VERSION 5.8 ;
BUSBITCHARS "[]" ;
DIVIDERCHAR "/" ;
UNITS
    DATABASE MICRONS 1000 ;
END UNITS

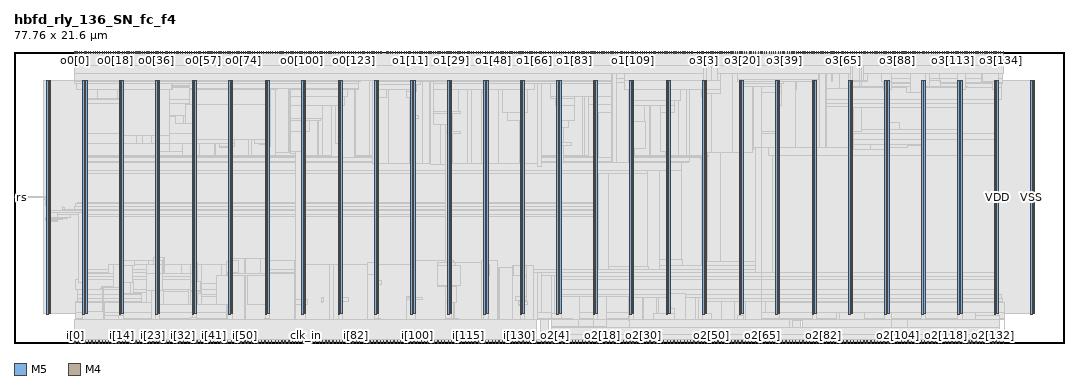
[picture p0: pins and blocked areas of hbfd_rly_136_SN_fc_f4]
MACRO hbfd_rly_136_SN_fc_f4
  FOREIGN hbfd_rly_136_SN_fc_f4 0 0 ;
  CLASS BLOCK ;
  SIZE 77.76 BY 21.6 ;
  PIN clk_in
    DIRECTION INPUT ;
    USE SIGNAL ;
    PORT
      LAYER M5 ;
        RECT  21.6 0 21.624 0.192 ;
    END
  END clk_in
  PIN clk_out0
    DIRECTION OUTPUT ;
    USE SIGNAL ;
    PORT
      LAYER M5 ;
        RECT  15.84 21.408 15.864 21.6 ;
    END
  END clk_out0
  PIN clk_out1
    DIRECTION OUTPUT ;
    USE SIGNAL ;
    PORT
      LAYER M5 ;
        RECT  38.88 21.408 38.904 21.6 ;
    END
  END clk_out1
  PIN clk_out2
    DIRECTION OUTPUT ;
    USE SIGNAL ;
    PORT
      LAYER M5 ;
        RECT  56.16 0 56.184 0.192 ;
    END
  END clk_out2
  PIN clk_out3
    DIRECTION OUTPUT ;
    USE SIGNAL ;
    PORT
      LAYER M5 ;
        RECT  61.92 21.408 61.944 21.6 ;
    END
  END clk_out3
  PIN i[0]
    DIRECTION INPUT ;
    USE SIGNAL ;
    PORT
      LAYER M5 ;
        RECT  4.512 0 4.536 0.192 ;
    END
  END i[0]
  PIN i[100]
    DIRECTION INPUT ;
    USE SIGNAL ;
    PORT
      LAYER M5 ;
        RECT  29.856 0 29.88 0.192 ;
    END
  END i[100]
  PIN i[101]
    DIRECTION INPUT ;
    USE SIGNAL ;
    PORT
      LAYER M5 ;
        RECT  30.144 0 30.168 0.192 ;
    END
  END i[101]
  PIN i[102]
    DIRECTION INPUT ;
    USE SIGNAL ;
    PORT
      LAYER M5 ;
        RECT  30.384 0 30.408 0.192 ;
    END
  END i[102]
  PIN i[103]
    DIRECTION INPUT ;
    USE SIGNAL ;
    PORT
      LAYER M5 ;
        RECT  30.624 0 30.648 0.192 ;
    END
  END i[103]
  PIN i[104]
    DIRECTION INPUT ;
    USE SIGNAL ;
    PORT
      LAYER M5 ;
        RECT  30.864 0 30.888 0.192 ;
    END
  END i[104]
  PIN i[105]
    DIRECTION INPUT ;
    USE SIGNAL ;
    PORT
      LAYER M5 ;
        RECT  31.152 0 31.176 0.192 ;
    END
  END i[105]
  PIN i[106]
    DIRECTION INPUT ;
    USE SIGNAL ;
    PORT
      LAYER M5 ;
        RECT  31.392 0 31.416 0.192 ;
    END
  END i[106]
  PIN i[107]
    DIRECTION INPUT ;
    USE SIGNAL ;
    PORT
      LAYER M5 ;
        RECT  31.632 0 31.656 0.192 ;
    END
  END i[107]
  PIN i[108]
    DIRECTION INPUT ;
    USE SIGNAL ;
    PORT
      LAYER M5 ;
        RECT  31.872 0 31.896 0.192 ;
    END
  END i[108]
  PIN i[109]
    DIRECTION INPUT ;
    USE SIGNAL ;
    PORT
      LAYER M5 ;
        RECT  32.16 0 32.184 0.192 ;
    END
  END i[109]
  PIN i[10]
    DIRECTION INPUT ;
    USE SIGNAL ;
    PORT
      LAYER M5 ;
        RECT  7.008 0 7.032 0.192 ;
    END
  END i[10]
  PIN i[110]
    DIRECTION INPUT ;
    USE SIGNAL ;
    PORT
      LAYER M5 ;
        RECT  32.4 0 32.424 0.192 ;
    END
  END i[110]
  PIN i[111]
    DIRECTION INPUT ;
    USE SIGNAL ;
    PORT
      LAYER M5 ;
        RECT  32.64 0 32.664 0.192 ;
    END
  END i[111]
  PIN i[112]
    DIRECTION INPUT ;
    USE SIGNAL ;
    PORT
      LAYER M5 ;
        RECT  32.88 0 32.904 0.192 ;
    END
  END i[112]
  PIN i[113]
    DIRECTION INPUT ;
    USE SIGNAL ;
    PORT
      LAYER M5 ;
        RECT  33.12 0 33.144 0.192 ;
    END
  END i[113]
  PIN i[114]
    DIRECTION INPUT ;
    USE SIGNAL ;
    PORT
      LAYER M5 ;
        RECT  33.408 0 33.432 0.192 ;
    END
  END i[114]
  PIN i[115]
    DIRECTION INPUT ;
    USE SIGNAL ;
    PORT
      LAYER M5 ;
        RECT  33.648 0 33.672 0.192 ;
    END
  END i[115]
  PIN i[116]
    DIRECTION INPUT ;
    USE SIGNAL ;
    PORT
      LAYER M5 ;
        RECT  33.888 0 33.912 0.192 ;
    END
  END i[116]
  PIN i[117]
    DIRECTION INPUT ;
    USE SIGNAL ;
    PORT
      LAYER M5 ;
        RECT  34.128 0 34.152 0.192 ;
    END
  END i[117]
  PIN i[118]
    DIRECTION INPUT ;
    USE SIGNAL ;
    PORT
      LAYER M5 ;
        RECT  34.416 0 34.44 0.192 ;
    END
  END i[118]
  PIN i[119]
    DIRECTION INPUT ;
    USE SIGNAL ;
    PORT
      LAYER M5 ;
        RECT  34.656 0 34.68 0.192 ;
    END
  END i[119]
  PIN i[11]
    DIRECTION INPUT ;
    USE SIGNAL ;
    PORT
      LAYER M5 ;
        RECT  7.248 0 7.272 0.192 ;
    END
  END i[11]
  PIN i[120]
    DIRECTION INPUT ;
    USE SIGNAL ;
    PORT
      LAYER M5 ;
        RECT  34.896 0 34.92 0.192 ;
    END
  END i[120]
  PIN i[121]
    DIRECTION INPUT ;
    USE SIGNAL ;
    PORT
      LAYER M5 ;
        RECT  35.136 0 35.16 0.192 ;
    END
  END i[121]
  PIN i[122]
    DIRECTION INPUT ;
    USE SIGNAL ;
    PORT
      LAYER M5 ;
        RECT  35.424 0 35.448 0.192 ;
    END
  END i[122]
  PIN i[123]
    DIRECTION INPUT ;
    USE SIGNAL ;
    PORT
      LAYER M5 ;
        RECT  35.664 0 35.688 0.192 ;
    END
  END i[123]
  PIN i[124]
    DIRECTION INPUT ;
    USE SIGNAL ;
    PORT
      LAYER M5 ;
        RECT  35.904 0 35.928 0.192 ;
    END
  END i[124]
  PIN i[125]
    DIRECTION INPUT ;
    USE SIGNAL ;
    PORT
      LAYER M5 ;
        RECT  36.144 0 36.168 0.192 ;
    END
  END i[125]
  PIN i[126]
    DIRECTION INPUT ;
    USE SIGNAL ;
    PORT
      LAYER M5 ;
        RECT  36.384 0 36.408 0.192 ;
    END
  END i[126]
  PIN i[127]
    DIRECTION INPUT ;
    USE SIGNAL ;
    PORT
      LAYER M5 ;
        RECT  36.672 0 36.696 0.192 ;
    END
  END i[127]
  PIN i[128]
    DIRECTION INPUT ;
    USE SIGNAL ;
    PORT
      LAYER M5 ;
        RECT  36.912 0 36.936 0.192 ;
    END
  END i[128]
  PIN i[129]
    DIRECTION INPUT ;
    USE SIGNAL ;
    PORT
      LAYER M5 ;
        RECT  37.152 0 37.176 0.192 ;
    END
  END i[129]
  PIN i[12]
    DIRECTION INPUT ;
    USE SIGNAL ;
    PORT
      LAYER M5 ;
        RECT  7.536 0 7.56 0.192 ;
    END
  END i[12]
  PIN i[130]
    DIRECTION INPUT ;
    USE SIGNAL ;
    PORT
      LAYER M5 ;
        RECT  37.392 0 37.416 0.192 ;
    END
  END i[130]
  PIN i[131]
    DIRECTION INPUT ;
    USE SIGNAL ;
    PORT
      LAYER M5 ;
        RECT  37.68 0 37.704 0.192 ;
    END
  END i[131]
  PIN i[132]
    DIRECTION INPUT ;
    USE SIGNAL ;
    PORT
      LAYER M5 ;
        RECT  37.92 0 37.944 0.192 ;
    END
  END i[132]
  PIN i[133]
    DIRECTION INPUT ;
    USE SIGNAL ;
    PORT
      LAYER M5 ;
        RECT  38.16 0 38.184 0.192 ;
    END
  END i[133]
  PIN i[134]
    DIRECTION INPUT ;
    USE SIGNAL ;
    PORT
      LAYER M5 ;
        RECT  38.4 0 38.424 0.192 ;
    END
  END i[134]
  PIN i[135]
    DIRECTION INPUT ;
    USE SIGNAL ;
    PORT
      LAYER M5 ;
        RECT  38.688 0 38.712 0.192 ;
    END
  END i[135]
  PIN i[13]
    DIRECTION INPUT ;
    USE SIGNAL ;
    PORT
      LAYER M5 ;
        RECT  7.776 0 7.8 0.192 ;
    END
  END i[13]
  PIN i[14]
    DIRECTION INPUT ;
    USE SIGNAL ;
    PORT
      LAYER M5 ;
        RECT  8.016 0 8.04 0.192 ;
    END
  END i[14]
  PIN i[15]
    DIRECTION INPUT ;
    USE SIGNAL ;
    PORT
      LAYER M5 ;
        RECT  8.256 0 8.28 0.192 ;
    END
  END i[15]
  PIN i[16]
    DIRECTION INPUT ;
    USE SIGNAL ;
    PORT
      LAYER M5 ;
        RECT  8.544 0 8.568 0.192 ;
    END
  END i[16]
  PIN i[17]
    DIRECTION INPUT ;
    USE SIGNAL ;
    PORT
      LAYER M5 ;
        RECT  8.784 0 8.808 0.192 ;
    END
  END i[17]
  PIN i[18]
    DIRECTION INPUT ;
    USE SIGNAL ;
    PORT
      LAYER M5 ;
        RECT  9.024 0 9.048 0.192 ;
    END
  END i[18]
  PIN i[19]
    DIRECTION INPUT ;
    USE SIGNAL ;
    PORT
      LAYER M5 ;
        RECT  9.264 0 9.288 0.192 ;
    END
  END i[19]
  PIN i[1]
    DIRECTION INPUT ;
    USE SIGNAL ;
    PORT
      LAYER M5 ;
        RECT  4.752 0 4.776 0.192 ;
    END
  END i[1]
  PIN i[20]
    DIRECTION INPUT ;
    USE SIGNAL ;
    PORT
      LAYER M5 ;
        RECT  9.552 0 9.576 0.192 ;
    END
  END i[20]
  PIN i[21]
    DIRECTION INPUT ;
    USE SIGNAL ;
    PORT
      LAYER M5 ;
        RECT  9.792 0 9.816 0.192 ;
    END
  END i[21]
  PIN i[22]
    DIRECTION INPUT ;
    USE SIGNAL ;
    PORT
      LAYER M5 ;
        RECT  10.032 0 10.056 0.192 ;
    END
  END i[22]
  PIN i[23]
    DIRECTION INPUT ;
    USE SIGNAL ;
    PORT
      LAYER M5 ;
        RECT  10.272 0 10.296 0.192 ;
    END
  END i[23]
  PIN i[24]
    DIRECTION INPUT ;
    USE SIGNAL ;
    PORT
      LAYER M5 ;
        RECT  10.56 0 10.584 0.192 ;
    END
  END i[24]
  PIN i[25]
    DIRECTION INPUT ;
    USE SIGNAL ;
    PORT
      LAYER M5 ;
        RECT  10.8 0 10.824 0.192 ;
    END
  END i[25]
  PIN i[26]
    DIRECTION INPUT ;
    USE SIGNAL ;
    PORT
      LAYER M5 ;
        RECT  11.04 0 11.064 0.192 ;
    END
  END i[26]
  PIN i[27]
    DIRECTION INPUT ;
    USE SIGNAL ;
    PORT
      LAYER M5 ;
        RECT  11.28 0 11.304 0.192 ;
    END
  END i[27]
  PIN i[28]
    DIRECTION INPUT ;
    USE SIGNAL ;
    PORT
      LAYER M5 ;
        RECT  11.52 0 11.544 0.192 ;
    END
  END i[28]
  PIN i[29]
    DIRECTION INPUT ;
    USE SIGNAL ;
    PORT
      LAYER M5 ;
        RECT  11.808 0 11.832 0.192 ;
    END
  END i[29]
  PIN i[2]
    DIRECTION INPUT ;
    USE SIGNAL ;
    PORT
      LAYER M5 ;
        RECT  4.992 0 5.016 0.192 ;
    END
  END i[2]
  PIN i[30]
    DIRECTION INPUT ;
    USE SIGNAL ;
    PORT
      LAYER M5 ;
        RECT  12.048 0 12.072 0.192 ;
    END
  END i[30]
  PIN i[31]
    DIRECTION INPUT ;
    USE SIGNAL ;
    PORT
      LAYER M5 ;
        RECT  12.288 0 12.312 0.192 ;
    END
  END i[31]
  PIN i[32]
    DIRECTION INPUT ;
    USE SIGNAL ;
    PORT
      LAYER M5 ;
        RECT  12.528 0 12.552 0.192 ;
    END
  END i[32]
  PIN i[33]
    DIRECTION INPUT ;
    USE SIGNAL ;
    PORT
      LAYER M5 ;
        RECT  12.816 0 12.84 0.192 ;
    END
  END i[33]
  PIN i[34]
    DIRECTION INPUT ;
    USE SIGNAL ;
    PORT
      LAYER M5 ;
        RECT  13.056 0 13.08 0.192 ;
    END
  END i[34]
  PIN i[35]
    DIRECTION INPUT ;
    USE SIGNAL ;
    PORT
      LAYER M5 ;
        RECT  13.296 0 13.32 0.192 ;
    END
  END i[35]
  PIN i[36]
    DIRECTION INPUT ;
    USE SIGNAL ;
    PORT
      LAYER M5 ;
        RECT  13.536 0 13.56 0.192 ;
    END
  END i[36]
  PIN i[37]
    DIRECTION INPUT ;
    USE SIGNAL ;
    PORT
      LAYER M5 ;
        RECT  13.824 0 13.848 0.192 ;
    END
  END i[37]
  PIN i[38]
    DIRECTION INPUT ;
    USE SIGNAL ;
    PORT
      LAYER M5 ;
        RECT  14.064 0 14.088 0.192 ;
    END
  END i[38]
  PIN i[39]
    DIRECTION INPUT ;
    USE SIGNAL ;
    PORT
      LAYER M5 ;
        RECT  14.304 0 14.328 0.192 ;
    END
  END i[39]
  PIN i[3]
    DIRECTION INPUT ;
    USE SIGNAL ;
    PORT
      LAYER M5 ;
        RECT  5.28 0 5.304 0.192 ;
    END
  END i[3]
  PIN i[40]
    DIRECTION INPUT ;
    USE SIGNAL ;
    PORT
      LAYER M5 ;
        RECT  14.544 0 14.568 0.192 ;
    END
  END i[40]
  PIN i[41]
    DIRECTION INPUT ;
    USE SIGNAL ;
    PORT
      LAYER M5 ;
        RECT  14.784 0 14.808 0.192 ;
    END
  END i[41]
  PIN i[42]
    DIRECTION INPUT ;
    USE SIGNAL ;
    PORT
      LAYER M5 ;
        RECT  15.072 0 15.096 0.192 ;
    END
  END i[42]
  PIN i[43]
    DIRECTION INPUT ;
    USE SIGNAL ;
    PORT
      LAYER M5 ;
        RECT  15.312 0 15.336 0.192 ;
    END
  END i[43]
  PIN i[44]
    DIRECTION INPUT ;
    USE SIGNAL ;
    PORT
      LAYER M5 ;
        RECT  15.552 0 15.576 0.192 ;
    END
  END i[44]
  PIN i[45]
    DIRECTION INPUT ;
    USE SIGNAL ;
    PORT
      LAYER M5 ;
        RECT  15.792 0 15.816 0.192 ;
    END
  END i[45]
  PIN i[46]
    DIRECTION INPUT ;
    USE SIGNAL ;
    PORT
      LAYER M5 ;
        RECT  16.08 0 16.104 0.192 ;
    END
  END i[46]
  PIN i[47]
    DIRECTION INPUT ;
    USE SIGNAL ;
    PORT
      LAYER M5 ;
        RECT  16.32 0 16.344 0.192 ;
    END
  END i[47]
  PIN i[48]
    DIRECTION INPUT ;
    USE SIGNAL ;
    PORT
      LAYER M5 ;
        RECT  16.56 0 16.584 0.192 ;
    END
  END i[48]
  PIN i[49]
    DIRECTION INPUT ;
    USE SIGNAL ;
    PORT
      LAYER M5 ;
        RECT  16.8 0 16.824 0.192 ;
    END
  END i[49]
  PIN i[4]
    DIRECTION INPUT ;
    USE SIGNAL ;
    PORT
      LAYER M5 ;
        RECT  5.52 0 5.544 0.192 ;
    END
  END i[4]
  PIN i[50]
    DIRECTION INPUT ;
    USE SIGNAL ;
    PORT
      LAYER M5 ;
        RECT  17.088 0 17.112 0.192 ;
    END
  END i[50]
  PIN i[51]
    DIRECTION INPUT ;
    USE SIGNAL ;
    PORT
      LAYER M5 ;
        RECT  17.328 0 17.352 0.192 ;
    END
  END i[51]
  PIN i[52]
    DIRECTION INPUT ;
    USE SIGNAL ;
    PORT
      LAYER M5 ;
        RECT  17.568 0 17.592 0.192 ;
    END
  END i[52]
  PIN i[53]
    DIRECTION INPUT ;
    USE SIGNAL ;
    PORT
      LAYER M5 ;
        RECT  17.808 0 17.832 0.192 ;
    END
  END i[53]
  PIN i[54]
    DIRECTION INPUT ;
    USE SIGNAL ;
    PORT
      LAYER M5 ;
        RECT  18.048 0 18.072 0.192 ;
    END
  END i[54]
  PIN i[55]
    DIRECTION INPUT ;
    USE SIGNAL ;
    PORT
      LAYER M5 ;
        RECT  18.336 0 18.36 0.192 ;
    END
  END i[55]
  PIN i[56]
    DIRECTION INPUT ;
    USE SIGNAL ;
    PORT
      LAYER M5 ;
        RECT  18.576 0 18.6 0.192 ;
    END
  END i[56]
  PIN i[57]
    DIRECTION INPUT ;
    USE SIGNAL ;
    PORT
      LAYER M5 ;
        RECT  18.816 0 18.84 0.192 ;
    END
  END i[57]
  PIN i[58]
    DIRECTION INPUT ;
    USE SIGNAL ;
    PORT
      LAYER M5 ;
        RECT  19.056 0 19.08 0.192 ;
    END
  END i[58]
  PIN i[59]
    DIRECTION INPUT ;
    USE SIGNAL ;
    PORT
      LAYER M5 ;
        RECT  19.344 0 19.368 0.192 ;
    END
  END i[59]
  PIN i[5]
    DIRECTION INPUT ;
    USE SIGNAL ;
    PORT
      LAYER M5 ;
        RECT  5.76 0 5.784 0.192 ;
    END
  END i[5]
  PIN i[60]
    DIRECTION INPUT ;
    USE SIGNAL ;
    PORT
      LAYER M5 ;
        RECT  19.584 0 19.608 0.192 ;
    END
  END i[60]
  PIN i[61]
    DIRECTION INPUT ;
    USE SIGNAL ;
    PORT
      LAYER M5 ;
        RECT  19.824 0 19.848 0.192 ;
    END
  END i[61]
  PIN i[62]
    DIRECTION INPUT ;
    USE SIGNAL ;
    PORT
      LAYER M5 ;
        RECT  20.064 0 20.088 0.192 ;
    END
  END i[62]
  PIN i[63]
    DIRECTION INPUT ;
    USE SIGNAL ;
    PORT
      LAYER M5 ;
        RECT  20.352 0 20.376 0.192 ;
    END
  END i[63]
  PIN i[64]
    DIRECTION INPUT ;
    USE SIGNAL ;
    PORT
      LAYER M5 ;
        RECT  20.592 0 20.616 0.192 ;
    END
  END i[64]
  PIN i[65]
    DIRECTION INPUT ;
    USE SIGNAL ;
    PORT
      LAYER M5 ;
        RECT  20.832 0 20.856 0.192 ;
    END
  END i[65]
  PIN i[66]
    DIRECTION INPUT ;
    USE SIGNAL ;
    PORT
      LAYER M5 ;
        RECT  21.072 0 21.096 0.192 ;
    END
  END i[66]
  PIN i[67]
    DIRECTION INPUT ;
    USE SIGNAL ;
    PORT
      LAYER M5 ;
        RECT  21.36 0 21.384 0.192 ;
    END
  END i[67]
  PIN i[68]
    DIRECTION INPUT ;
    USE SIGNAL ;
    PORT
      LAYER M5 ;
        RECT  21.84 0 21.864 0.192 ;
    END
  END i[68]
  PIN i[69]
    DIRECTION INPUT ;
    USE SIGNAL ;
    PORT
      LAYER M5 ;
        RECT  22.08 0 22.104 0.192 ;
    END
  END i[69]
  PIN i[6]
    DIRECTION INPUT ;
    USE SIGNAL ;
    PORT
      LAYER M5 ;
        RECT  6 0 6.024 0.192 ;
    END
  END i[6]
  PIN i[70]
    DIRECTION INPUT ;
    USE SIGNAL ;
    PORT
      LAYER M5 ;
        RECT  22.32 0 22.344 0.192 ;
    END
  END i[70]
  PIN i[71]
    DIRECTION INPUT ;
    USE SIGNAL ;
    PORT
      LAYER M5 ;
        RECT  22.608 0 22.632 0.192 ;
    END
  END i[71]
  PIN i[72]
    DIRECTION INPUT ;
    USE SIGNAL ;
    PORT
      LAYER M5 ;
        RECT  22.848 0 22.872 0.192 ;
    END
  END i[72]
  PIN i[73]
    DIRECTION INPUT ;
    USE SIGNAL ;
    PORT
      LAYER M5 ;
        RECT  23.088 0 23.112 0.192 ;
    END
  END i[73]
  PIN i[74]
    DIRECTION INPUT ;
    USE SIGNAL ;
    PORT
      LAYER M5 ;
        RECT  23.328 0 23.352 0.192 ;
    END
  END i[74]
  PIN i[75]
    DIRECTION INPUT ;
    USE SIGNAL ;
    PORT
      LAYER M5 ;
        RECT  23.616 0 23.64 0.192 ;
    END
  END i[75]
  PIN i[76]
    DIRECTION INPUT ;
    USE SIGNAL ;
    PORT
      LAYER M5 ;
        RECT  23.856 0 23.88 0.192 ;
    END
  END i[76]
  PIN i[77]
    DIRECTION INPUT ;
    USE SIGNAL ;
    PORT
      LAYER M5 ;
        RECT  24.096 0 24.12 0.192 ;
    END
  END i[77]
  PIN i[78]
    DIRECTION INPUT ;
    USE SIGNAL ;
    PORT
      LAYER M5 ;
        RECT  24.336 0 24.36 0.192 ;
    END
  END i[78]
  PIN i[79]
    DIRECTION INPUT ;
    USE SIGNAL ;
    PORT
      LAYER M5 ;
        RECT  24.624 0 24.648 0.192 ;
    END
  END i[79]
  PIN i[7]
    DIRECTION INPUT ;
    USE SIGNAL ;
    PORT
      LAYER M5 ;
        RECT  6.288 0 6.312 0.192 ;
    END
  END i[7]
  PIN i[80]
    DIRECTION INPUT ;
    USE SIGNAL ;
    PORT
      LAYER M5 ;
        RECT  24.864 0 24.888 0.192 ;
    END
  END i[80]
  PIN i[81]
    DIRECTION INPUT ;
    USE SIGNAL ;
    PORT
      LAYER M5 ;
        RECT  25.104 0 25.128 0.192 ;
    END
  END i[81]
  PIN i[82]
    DIRECTION INPUT ;
    USE SIGNAL ;
    PORT
      LAYER M5 ;
        RECT  25.344 0 25.368 0.192 ;
    END
  END i[82]
  PIN i[83]
    DIRECTION INPUT ;
    USE SIGNAL ;
    PORT
      LAYER M5 ;
        RECT  25.584 0 25.608 0.192 ;
    END
  END i[83]
  PIN i[84]
    DIRECTION INPUT ;
    USE SIGNAL ;
    PORT
      LAYER M5 ;
        RECT  25.872 0 25.896 0.192 ;
    END
  END i[84]
  PIN i[85]
    DIRECTION INPUT ;
    USE SIGNAL ;
    PORT
      LAYER M5 ;
        RECT  26.112 0 26.136 0.192 ;
    END
  END i[85]
  PIN i[86]
    DIRECTION INPUT ;
    USE SIGNAL ;
    PORT
      LAYER M5 ;
        RECT  26.352 0 26.376 0.192 ;
    END
  END i[86]
  PIN i[87]
    DIRECTION INPUT ;
    USE SIGNAL ;
    PORT
      LAYER M5 ;
        RECT  26.592 0 26.616 0.192 ;
    END
  END i[87]
  PIN i[88]
    DIRECTION INPUT ;
    USE SIGNAL ;
    PORT
      LAYER M5 ;
        RECT  26.88 0 26.904 0.192 ;
    END
  END i[88]
  PIN i[89]
    DIRECTION INPUT ;
    USE SIGNAL ;
    PORT
      LAYER M5 ;
        RECT  27.12 0 27.144 0.192 ;
    END
  END i[89]
  PIN i[8]
    DIRECTION INPUT ;
    USE SIGNAL ;
    PORT
      LAYER M5 ;
        RECT  6.528 0 6.552 0.192 ;
    END
  END i[8]
  PIN i[90]
    DIRECTION INPUT ;
    USE SIGNAL ;
    PORT
      LAYER M5 ;
        RECT  27.36 0 27.384 0.192 ;
    END
  END i[90]
  PIN i[91]
    DIRECTION INPUT ;
    USE SIGNAL ;
    PORT
      LAYER M5 ;
        RECT  27.6 0 27.624 0.192 ;
    END
  END i[91]
  PIN i[92]
    DIRECTION INPUT ;
    USE SIGNAL ;
    PORT
      LAYER M5 ;
        RECT  27.888 0 27.912 0.192 ;
    END
  END i[92]
  PIN i[93]
    DIRECTION INPUT ;
    USE SIGNAL ;
    PORT
      LAYER M5 ;
        RECT  28.128 0 28.152 0.192 ;
    END
  END i[93]
  PIN i[94]
    DIRECTION INPUT ;
    USE SIGNAL ;
    PORT
      LAYER M5 ;
        RECT  28.368 0 28.392 0.192 ;
    END
  END i[94]
  PIN i[95]
    DIRECTION INPUT ;
    USE SIGNAL ;
    PORT
      LAYER M5 ;
        RECT  28.608 0 28.632 0.192 ;
    END
  END i[95]
  PIN i[96]
    DIRECTION INPUT ;
    USE SIGNAL ;
    PORT
      LAYER M5 ;
        RECT  28.896 0 28.92 0.192 ;
    END
  END i[96]
  PIN i[97]
    DIRECTION INPUT ;
    USE SIGNAL ;
    PORT
      LAYER M5 ;
        RECT  29.136 0 29.16 0.192 ;
    END
  END i[97]
  PIN i[98]
    DIRECTION INPUT ;
    USE SIGNAL ;
    PORT
      LAYER M5 ;
        RECT  29.376 0 29.4 0.192 ;
    END
  END i[98]
  PIN i[99]
    DIRECTION INPUT ;
    USE SIGNAL ;
    PORT
      LAYER M5 ;
        RECT  29.616 0 29.64 0.192 ;
    END
  END i[99]
  PIN i[9]
    DIRECTION INPUT ;
    USE SIGNAL ;
    PORT
      LAYER M5 ;
        RECT  6.768 0 6.792 0.192 ;
    END
  END i[9]
  PIN o0[0]
    DIRECTION OUTPUT ;
    USE SIGNAL ;
    PORT
      LAYER M5 ;
        RECT  4.512 21.408 4.536 21.6 ;
    END
  END o0[0]
  PIN o0[100]
    DIRECTION OUTPUT ;
    USE SIGNAL ;
    PORT
      LAYER M5 ;
        RECT  21.312 21.408 21.336 21.6 ;
    END
  END o0[100]
  PIN o0[101]
    DIRECTION OUTPUT ;
    USE SIGNAL ;
    PORT
      LAYER M5 ;
        RECT  21.504 21.408 21.528 21.6 ;
    END
  END o0[101]
  PIN o0[102]
    DIRECTION OUTPUT ;
    USE SIGNAL ;
    PORT
      LAYER M5 ;
        RECT  21.648 21.408 21.672 21.6 ;
    END
  END o0[102]
  PIN o0[103]
    DIRECTION OUTPUT ;
    USE SIGNAL ;
    PORT
      LAYER M5 ;
        RECT  21.84 21.408 21.864 21.6 ;
    END
  END o0[103]
  PIN o0[104]
    DIRECTION OUTPUT ;
    USE SIGNAL ;
    PORT
      LAYER M5 ;
        RECT  21.984 21.408 22.008 21.6 ;
    END
  END o0[104]
  PIN o0[105]
    DIRECTION OUTPUT ;
    USE SIGNAL ;
    PORT
      LAYER M5 ;
        RECT  22.176 21.408 22.2 21.6 ;
    END
  END o0[105]
  PIN o0[106]
    DIRECTION OUTPUT ;
    USE SIGNAL ;
    PORT
      LAYER M5 ;
        RECT  22.32 21.408 22.344 21.6 ;
    END
  END o0[106]
  PIN o0[107]
    DIRECTION OUTPUT ;
    USE SIGNAL ;
    PORT
      LAYER M5 ;
        RECT  22.464 21.408 22.488 21.6 ;
    END
  END o0[107]
  PIN o0[108]
    DIRECTION OUTPUT ;
    USE SIGNAL ;
    PORT
      LAYER M5 ;
        RECT  22.656 21.408 22.68 21.6 ;
    END
  END o0[108]
  PIN o0[109]
    DIRECTION OUTPUT ;
    USE SIGNAL ;
    PORT
      LAYER M5 ;
        RECT  22.8 21.408 22.824 21.6 ;
    END
  END o0[109]
  PIN o0[10]
    DIRECTION OUTPUT ;
    USE SIGNAL ;
    PORT
      LAYER M5 ;
        RECT  6.192 21.408 6.216 21.6 ;
    END
  END o0[10]
  PIN o0[110]
    DIRECTION OUTPUT ;
    USE SIGNAL ;
    PORT
      LAYER M5 ;
        RECT  22.992 21.408 23.016 21.6 ;
    END
  END o0[110]
  PIN o0[111]
    DIRECTION OUTPUT ;
    USE SIGNAL ;
    PORT
      LAYER M5 ;
        RECT  23.136 21.408 23.16 21.6 ;
    END
  END o0[111]
  PIN o0[112]
    DIRECTION OUTPUT ;
    USE SIGNAL ;
    PORT
      LAYER M5 ;
        RECT  23.328 21.408 23.352 21.6 ;
    END
  END o0[112]
  PIN o0[113]
    DIRECTION OUTPUT ;
    USE SIGNAL ;
    PORT
      LAYER M5 ;
        RECT  23.472 21.408 23.496 21.6 ;
    END
  END o0[113]
  PIN o0[114]
    DIRECTION OUTPUT ;
    USE SIGNAL ;
    PORT
      LAYER M5 ;
        RECT  23.664 21.408 23.688 21.6 ;
    END
  END o0[114]
  PIN o0[115]
    DIRECTION OUTPUT ;
    USE SIGNAL ;
    PORT
      LAYER M5 ;
        RECT  23.808 21.408 23.832 21.6 ;
    END
  END o0[115]
  PIN o0[116]
    DIRECTION OUTPUT ;
    USE SIGNAL ;
    PORT
      LAYER M5 ;
        RECT  24 21.408 24.024 21.6 ;
    END
  END o0[116]
  PIN o0[117]
    DIRECTION OUTPUT ;
    USE SIGNAL ;
    PORT
      LAYER M5 ;
        RECT  24.144 21.408 24.168 21.6 ;
    END
  END o0[117]
  PIN o0[118]
    DIRECTION OUTPUT ;
    USE SIGNAL ;
    PORT
      LAYER M5 ;
        RECT  24.336 21.408 24.36 21.6 ;
    END
  END o0[118]
  PIN o0[119]
    DIRECTION OUTPUT ;
    USE SIGNAL ;
    PORT
      LAYER M5 ;
        RECT  24.48 21.408 24.504 21.6 ;
    END
  END o0[119]
  PIN o0[11]
    DIRECTION OUTPUT ;
    USE SIGNAL ;
    PORT
      LAYER M5 ;
        RECT  6.336 21.408 6.36 21.6 ;
    END
  END o0[11]
  PIN o0[120]
    DIRECTION OUTPUT ;
    USE SIGNAL ;
    PORT
      LAYER M5 ;
        RECT  24.672 21.408 24.696 21.6 ;
    END
  END o0[120]
  PIN o0[121]
    DIRECTION OUTPUT ;
    USE SIGNAL ;
    PORT
      LAYER M5 ;
        RECT  24.816 21.408 24.84 21.6 ;
    END
  END o0[121]
  PIN o0[122]
    DIRECTION OUTPUT ;
    USE SIGNAL ;
    PORT
      LAYER M5 ;
        RECT  24.96 21.408 24.984 21.6 ;
    END
  END o0[122]
  PIN o0[123]
    DIRECTION OUTPUT ;
    USE SIGNAL ;
    PORT
      LAYER M5 ;
        RECT  25.152 21.408 25.176 21.6 ;
    END
  END o0[123]
  PIN o0[124]
    DIRECTION OUTPUT ;
    USE SIGNAL ;
    PORT
      LAYER M5 ;
        RECT  25.296 21.408 25.32 21.6 ;
    END
  END o0[124]
  PIN o0[125]
    DIRECTION OUTPUT ;
    USE SIGNAL ;
    PORT
      LAYER M5 ;
        RECT  25.488 21.408 25.512 21.6 ;
    END
  END o0[125]
  PIN o0[126]
    DIRECTION OUTPUT ;
    USE SIGNAL ;
    PORT
      LAYER M5 ;
        RECT  25.632 21.408 25.656 21.6 ;
    END
  END o0[126]
  PIN o0[127]
    DIRECTION OUTPUT ;
    USE SIGNAL ;
    PORT
      LAYER M5 ;
        RECT  25.824 21.408 25.848 21.6 ;
    END
  END o0[127]
  PIN o0[128]
    DIRECTION OUTPUT ;
    USE SIGNAL ;
    PORT
      LAYER M5 ;
        RECT  25.968 21.408 25.992 21.6 ;
    END
  END o0[128]
  PIN o0[129]
    DIRECTION OUTPUT ;
    USE SIGNAL ;
    PORT
      LAYER M5 ;
        RECT  26.16 21.408 26.184 21.6 ;
    END
  END o0[129]
  PIN o0[12]
    DIRECTION OUTPUT ;
    USE SIGNAL ;
    PORT
      LAYER M5 ;
        RECT  6.528 21.408 6.552 21.6 ;
    END
  END o0[12]
  PIN o0[130]
    DIRECTION OUTPUT ;
    USE SIGNAL ;
    PORT
      LAYER M5 ;
        RECT  26.304 21.408 26.328 21.6 ;
    END
  END o0[130]
  PIN o0[131]
    DIRECTION OUTPUT ;
    USE SIGNAL ;
    PORT
      LAYER M5 ;
        RECT  26.496 21.408 26.52 21.6 ;
    END
  END o0[131]
  PIN o0[132]
    DIRECTION OUTPUT ;
    USE SIGNAL ;
    PORT
      LAYER M5 ;
        RECT  26.64 21.408 26.664 21.6 ;
    END
  END o0[132]
  PIN o0[133]
    DIRECTION OUTPUT ;
    USE SIGNAL ;
    PORT
      LAYER M5 ;
        RECT  26.832 21.408 26.856 21.6 ;
    END
  END o0[133]
  PIN o0[134]
    DIRECTION OUTPUT ;
    USE SIGNAL ;
    PORT
      LAYER M5 ;
        RECT  26.976 21.408 27 21.6 ;
    END
  END o0[134]
  PIN o0[135]
    DIRECTION OUTPUT ;
    USE SIGNAL ;
    PORT
      LAYER M5 ;
        RECT  27.168 21.408 27.192 21.6 ;
    END
  END o0[135]
  PIN o0[13]
    DIRECTION OUTPUT ;
    USE SIGNAL ;
    PORT
      LAYER M5 ;
        RECT  6.672 21.408 6.696 21.6 ;
    END
  END o0[13]
  PIN o0[14]
    DIRECTION OUTPUT ;
    USE SIGNAL ;
    PORT
      LAYER M5 ;
        RECT  6.816 21.408 6.84 21.6 ;
    END
  END o0[14]
  PIN o0[15]
    DIRECTION OUTPUT ;
    USE SIGNAL ;
    PORT
      LAYER M5 ;
        RECT  7.008 21.408 7.032 21.6 ;
    END
  END o0[15]
  PIN o0[16]
    DIRECTION OUTPUT ;
    USE SIGNAL ;
    PORT
      LAYER M5 ;
        RECT  7.152 21.408 7.176 21.6 ;
    END
  END o0[16]
  PIN o0[17]
    DIRECTION OUTPUT ;
    USE SIGNAL ;
    PORT
      LAYER M5 ;
        RECT  7.344 21.408 7.368 21.6 ;
    END
  END o0[17]
  PIN o0[18]
    DIRECTION OUTPUT ;
    USE SIGNAL ;
    PORT
      LAYER M5 ;
        RECT  7.488 21.408 7.512 21.6 ;
    END
  END o0[18]
  PIN o0[19]
    DIRECTION OUTPUT ;
    USE SIGNAL ;
    PORT
      LAYER M5 ;
        RECT  7.68 21.408 7.704 21.6 ;
    END
  END o0[19]
  PIN o0[1]
    DIRECTION OUTPUT ;
    USE SIGNAL ;
    PORT
      LAYER M5 ;
        RECT  4.656 21.408 4.68 21.6 ;
    END
  END o0[1]
  PIN o0[20]
    DIRECTION OUTPUT ;
    USE SIGNAL ;
    PORT
      LAYER M5 ;
        RECT  7.824 21.408 7.848 21.6 ;
    END
  END o0[20]
  PIN o0[21]
    DIRECTION OUTPUT ;
    USE SIGNAL ;
    PORT
      LAYER M5 ;
        RECT  8.016 21.408 8.04 21.6 ;
    END
  END o0[21]
  PIN o0[22]
    DIRECTION OUTPUT ;
    USE SIGNAL ;
    PORT
      LAYER M5 ;
        RECT  8.16 21.408 8.184 21.6 ;
    END
  END o0[22]
  PIN o0[23]
    DIRECTION OUTPUT ;
    USE SIGNAL ;
    PORT
      LAYER M5 ;
        RECT  8.352 21.408 8.376 21.6 ;
    END
  END o0[23]
  PIN o0[24]
    DIRECTION OUTPUT ;
    USE SIGNAL ;
    PORT
      LAYER M5 ;
        RECT  8.496 21.408 8.52 21.6 ;
    END
  END o0[24]
  PIN o0[25]
    DIRECTION OUTPUT ;
    USE SIGNAL ;
    PORT
      LAYER M5 ;
        RECT  8.688 21.408 8.712 21.6 ;
    END
  END o0[25]
  PIN o0[26]
    DIRECTION OUTPUT ;
    USE SIGNAL ;
    PORT
      LAYER M5 ;
        RECT  8.832 21.408 8.856 21.6 ;
    END
  END o0[26]
  PIN o0[27]
    DIRECTION OUTPUT ;
    USE SIGNAL ;
    PORT
      LAYER M5 ;
        RECT  9.024 21.408 9.048 21.6 ;
    END
  END o0[27]
  PIN o0[28]
    DIRECTION OUTPUT ;
    USE SIGNAL ;
    PORT
      LAYER M5 ;
        RECT  9.168 21.408 9.192 21.6 ;
    END
  END o0[28]
  PIN o0[29]
    DIRECTION OUTPUT ;
    USE SIGNAL ;
    PORT
      LAYER M5 ;
        RECT  9.312 21.408 9.336 21.6 ;
    END
  END o0[29]
  PIN o0[2]
    DIRECTION OUTPUT ;
    USE SIGNAL ;
    PORT
      LAYER M5 ;
        RECT  4.848 21.408 4.872 21.6 ;
    END
  END o0[2]
  PIN o0[30]
    DIRECTION OUTPUT ;
    USE SIGNAL ;
    PORT
      LAYER M5 ;
        RECT  9.504 21.408 9.528 21.6 ;
    END
  END o0[30]
  PIN o0[31]
    DIRECTION OUTPUT ;
    USE SIGNAL ;
    PORT
      LAYER M5 ;
        RECT  9.648 21.408 9.672 21.6 ;
    END
  END o0[31]
  PIN o0[32]
    DIRECTION OUTPUT ;
    USE SIGNAL ;
    PORT
      LAYER M5 ;
        RECT  9.84 21.408 9.864 21.6 ;
    END
  END o0[32]
  PIN o0[33]
    DIRECTION OUTPUT ;
    USE SIGNAL ;
    PORT
      LAYER M5 ;
        RECT  9.984 21.408 10.008 21.6 ;
    END
  END o0[33]
  PIN o0[34]
    DIRECTION OUTPUT ;
    USE SIGNAL ;
    PORT
      LAYER M5 ;
        RECT  10.176 21.408 10.2 21.6 ;
    END
  END o0[34]
  PIN o0[35]
    DIRECTION OUTPUT ;
    USE SIGNAL ;
    PORT
      LAYER M5 ;
        RECT  10.32 21.408 10.344 21.6 ;
    END
  END o0[35]
  PIN o0[36]
    DIRECTION OUTPUT ;
    USE SIGNAL ;
    PORT
      LAYER M5 ;
        RECT  10.512 21.408 10.536 21.6 ;
    END
  END o0[36]
  PIN o0[37]
    DIRECTION OUTPUT ;
    USE SIGNAL ;
    PORT
      LAYER M5 ;
        RECT  10.656 21.408 10.68 21.6 ;
    END
  END o0[37]
  PIN o0[38]
    DIRECTION OUTPUT ;
    USE SIGNAL ;
    PORT
      LAYER M5 ;
        RECT  10.848 21.408 10.872 21.6 ;
    END
  END o0[38]
  PIN o0[39]
    DIRECTION OUTPUT ;
    USE SIGNAL ;
    PORT
      LAYER M5 ;
        RECT  10.992 21.408 11.016 21.6 ;
    END
  END o0[39]
  PIN o0[3]
    DIRECTION OUTPUT ;
    USE SIGNAL ;
    PORT
      LAYER M5 ;
        RECT  4.992 21.408 5.016 21.6 ;
    END
  END o0[3]
  PIN o0[40]
    DIRECTION OUTPUT ;
    USE SIGNAL ;
    PORT
      LAYER M5 ;
        RECT  11.184 21.408 11.208 21.6 ;
    END
  END o0[40]
  PIN o0[41]
    DIRECTION OUTPUT ;
    USE SIGNAL ;
    PORT
      LAYER M5 ;
        RECT  11.328 21.408 11.352 21.6 ;
    END
  END o0[41]
  PIN o0[42]
    DIRECTION OUTPUT ;
    USE SIGNAL ;
    PORT
      LAYER M5 ;
        RECT  11.52 21.408 11.544 21.6 ;
    END
  END o0[42]
  PIN o0[43]
    DIRECTION OUTPUT ;
    USE SIGNAL ;
    PORT
      LAYER M5 ;
        RECT  11.664 21.408 11.688 21.6 ;
    END
  END o0[43]
  PIN o0[44]
    DIRECTION OUTPUT ;
    USE SIGNAL ;
    PORT
      LAYER M5 ;
        RECT  11.856 21.408 11.88 21.6 ;
    END
  END o0[44]
  PIN o0[45]
    DIRECTION OUTPUT ;
    USE SIGNAL ;
    PORT
      LAYER M5 ;
        RECT  12 21.408 12.024 21.6 ;
    END
  END o0[45]
  PIN o0[46]
    DIRECTION OUTPUT ;
    USE SIGNAL ;
    PORT
      LAYER M5 ;
        RECT  12.144 21.408 12.168 21.6 ;
    END
  END o0[46]
  PIN o0[47]
    DIRECTION OUTPUT ;
    USE SIGNAL ;
    PORT
      LAYER M5 ;
        RECT  12.336 21.408 12.36 21.6 ;
    END
  END o0[47]
  PIN o0[48]
    DIRECTION OUTPUT ;
    USE SIGNAL ;
    PORT
      LAYER M5 ;
        RECT  12.48 21.408 12.504 21.6 ;
    END
  END o0[48]
  PIN o0[49]
    DIRECTION OUTPUT ;
    USE SIGNAL ;
    PORT
      LAYER M5 ;
        RECT  12.672 21.408 12.696 21.6 ;
    END
  END o0[49]
  PIN o0[4]
    DIRECTION OUTPUT ;
    USE SIGNAL ;
    PORT
      LAYER M5 ;
        RECT  5.184 21.408 5.208 21.6 ;
    END
  END o0[4]
  PIN o0[50]
    DIRECTION OUTPUT ;
    USE SIGNAL ;
    PORT
      LAYER M5 ;
        RECT  12.816 21.408 12.84 21.6 ;
    END
  END o0[50]
  PIN o0[51]
    DIRECTION OUTPUT ;
    USE SIGNAL ;
    PORT
      LAYER M5 ;
        RECT  13.008 21.408 13.032 21.6 ;
    END
  END o0[51]
  PIN o0[52]
    DIRECTION OUTPUT ;
    USE SIGNAL ;
    PORT
      LAYER M5 ;
        RECT  13.152 21.408 13.176 21.6 ;
    END
  END o0[52]
  PIN o0[53]
    DIRECTION OUTPUT ;
    USE SIGNAL ;
    PORT
      LAYER M5 ;
        RECT  13.344 21.408 13.368 21.6 ;
    END
  END o0[53]
  PIN o0[54]
    DIRECTION OUTPUT ;
    USE SIGNAL ;
    PORT
      LAYER M5 ;
        RECT  13.488 21.408 13.512 21.6 ;
    END
  END o0[54]
  PIN o0[55]
    DIRECTION OUTPUT ;
    USE SIGNAL ;
    PORT
      LAYER M5 ;
        RECT  13.68 21.408 13.704 21.6 ;
    END
  END o0[55]
  PIN o0[56]
    DIRECTION OUTPUT ;
    USE SIGNAL ;
    PORT
      LAYER M5 ;
        RECT  13.824 21.408 13.848 21.6 ;
    END
  END o0[56]
  PIN o0[57]
    DIRECTION OUTPUT ;
    USE SIGNAL ;
    PORT
      LAYER M5 ;
        RECT  14.016 21.408 14.04 21.6 ;
    END
  END o0[57]
  PIN o0[58]
    DIRECTION OUTPUT ;
    USE SIGNAL ;
    PORT
      LAYER M5 ;
        RECT  14.16 21.408 14.184 21.6 ;
    END
  END o0[58]
  PIN o0[59]
    DIRECTION OUTPUT ;
    USE SIGNAL ;
    PORT
      LAYER M5 ;
        RECT  14.352 21.408 14.376 21.6 ;
    END
  END o0[59]
  PIN o0[5]
    DIRECTION OUTPUT ;
    USE SIGNAL ;
    PORT
      LAYER M5 ;
        RECT  5.328 21.408 5.352 21.6 ;
    END
  END o0[5]
  PIN o0[60]
    DIRECTION OUTPUT ;
    USE SIGNAL ;
    PORT
      LAYER M5 ;
        RECT  14.496 21.408 14.52 21.6 ;
    END
  END o0[60]
  PIN o0[61]
    DIRECTION OUTPUT ;
    USE SIGNAL ;
    PORT
      LAYER M5 ;
        RECT  14.64 21.408 14.664 21.6 ;
    END
  END o0[61]
  PIN o0[62]
    DIRECTION OUTPUT ;
    USE SIGNAL ;
    PORT
      LAYER M5 ;
        RECT  14.832 21.408 14.856 21.6 ;
    END
  END o0[62]
  PIN o0[63]
    DIRECTION OUTPUT ;
    USE SIGNAL ;
    PORT
      LAYER M5 ;
        RECT  14.976 21.408 15 21.6 ;
    END
  END o0[63]
  PIN o0[64]
    DIRECTION OUTPUT ;
    USE SIGNAL ;
    PORT
      LAYER M5 ;
        RECT  15.168 21.408 15.192 21.6 ;
    END
  END o0[64]
  PIN o0[65]
    DIRECTION OUTPUT ;
    USE SIGNAL ;
    PORT
      LAYER M5 ;
        RECT  15.312 21.408 15.336 21.6 ;
    END
  END o0[65]
  PIN o0[66]
    DIRECTION OUTPUT ;
    USE SIGNAL ;
    PORT
      LAYER M5 ;
        RECT  15.504 21.408 15.528 21.6 ;
    END
  END o0[66]
  PIN o0[67]
    DIRECTION OUTPUT ;
    USE SIGNAL ;
    PORT
      LAYER M5 ;
        RECT  15.648 21.408 15.672 21.6 ;
    END
  END o0[67]
  PIN o0[68]
    DIRECTION OUTPUT ;
    USE SIGNAL ;
    PORT
      LAYER M5 ;
        RECT  15.984 21.408 16.008 21.6 ;
    END
  END o0[68]
  PIN o0[69]
    DIRECTION OUTPUT ;
    USE SIGNAL ;
    PORT
      LAYER M5 ;
        RECT  16.176 21.408 16.2 21.6 ;
    END
  END o0[69]
  PIN o0[6]
    DIRECTION OUTPUT ;
    USE SIGNAL ;
    PORT
      LAYER M5 ;
        RECT  5.52 21.408 5.544 21.6 ;
    END
  END o0[6]
  PIN o0[70]
    DIRECTION OUTPUT ;
    USE SIGNAL ;
    PORT
      LAYER M5 ;
        RECT  16.32 21.408 16.344 21.6 ;
    END
  END o0[70]
  PIN o0[71]
    DIRECTION OUTPUT ;
    USE SIGNAL ;
    PORT
      LAYER M5 ;
        RECT  16.512 21.408 16.536 21.6 ;
    END
  END o0[71]
  PIN o0[72]
    DIRECTION OUTPUT ;
    USE SIGNAL ;
    PORT
      LAYER M5 ;
        RECT  16.656 21.408 16.68 21.6 ;
    END
  END o0[72]
  PIN o0[73]
    DIRECTION OUTPUT ;
    USE SIGNAL ;
    PORT
      LAYER M5 ;
        RECT  16.848 21.408 16.872 21.6 ;
    END
  END o0[73]
  PIN o0[74]
    DIRECTION OUTPUT ;
    USE SIGNAL ;
    PORT
      LAYER M5 ;
        RECT  16.992 21.408 17.016 21.6 ;
    END
  END o0[74]
  PIN o0[75]
    DIRECTION OUTPUT ;
    USE SIGNAL ;
    PORT
      LAYER M5 ;
        RECT  17.136 21.408 17.16 21.6 ;
    END
  END o0[75]
  PIN o0[76]
    DIRECTION OUTPUT ;
    USE SIGNAL ;
    PORT
      LAYER M5 ;
        RECT  17.328 21.408 17.352 21.6 ;
    END
  END o0[76]
  PIN o0[77]
    DIRECTION OUTPUT ;
    USE SIGNAL ;
    PORT
      LAYER M5 ;
        RECT  17.472 21.408 17.496 21.6 ;
    END
  END o0[77]
  PIN o0[78]
    DIRECTION OUTPUT ;
    USE SIGNAL ;
    PORT
      LAYER M5 ;
        RECT  17.664 21.408 17.688 21.6 ;
    END
  END o0[78]
  PIN o0[79]
    DIRECTION OUTPUT ;
    USE SIGNAL ;
    PORT
      LAYER M5 ;
        RECT  17.808 21.408 17.832 21.6 ;
    END
  END o0[79]
  PIN o0[7]
    DIRECTION OUTPUT ;
    USE SIGNAL ;
    PORT
      LAYER M5 ;
        RECT  5.664 21.408 5.688 21.6 ;
    END
  END o0[7]
  PIN o0[80]
    DIRECTION OUTPUT ;
    USE SIGNAL ;
    PORT
      LAYER M5 ;
        RECT  18 21.408 18.024 21.6 ;
    END
  END o0[80]
  PIN o0[81]
    DIRECTION OUTPUT ;
    USE SIGNAL ;
    PORT
      LAYER M5 ;
        RECT  18.144 21.408 18.168 21.6 ;
    END
  END o0[81]
  PIN o0[82]
    DIRECTION OUTPUT ;
    USE SIGNAL ;
    PORT
      LAYER M5 ;
        RECT  18.336 21.408 18.36 21.6 ;
    END
  END o0[82]
  PIN o0[83]
    DIRECTION OUTPUT ;
    USE SIGNAL ;
    PORT
      LAYER M5 ;
        RECT  18.48 21.408 18.504 21.6 ;
    END
  END o0[83]
  PIN o0[84]
    DIRECTION OUTPUT ;
    USE SIGNAL ;
    PORT
      LAYER M5 ;
        RECT  18.672 21.408 18.696 21.6 ;
    END
  END o0[84]
  PIN o0[85]
    DIRECTION OUTPUT ;
    USE SIGNAL ;
    PORT
      LAYER M5 ;
        RECT  18.816 21.408 18.84 21.6 ;
    END
  END o0[85]
  PIN o0[86]
    DIRECTION OUTPUT ;
    USE SIGNAL ;
    PORT
      LAYER M5 ;
        RECT  19.008 21.408 19.032 21.6 ;
    END
  END o0[86]
  PIN o0[87]
    DIRECTION OUTPUT ;
    USE SIGNAL ;
    PORT
      LAYER M5 ;
        RECT  19.152 21.408 19.176 21.6 ;
    END
  END o0[87]
  PIN o0[88]
    DIRECTION OUTPUT ;
    USE SIGNAL ;
    PORT
      LAYER M5 ;
        RECT  19.344 21.408 19.368 21.6 ;
    END
  END o0[88]
  PIN o0[89]
    DIRECTION OUTPUT ;
    USE SIGNAL ;
    PORT
      LAYER M5 ;
        RECT  19.488 21.408 19.512 21.6 ;
    END
  END o0[89]
  PIN o0[8]
    DIRECTION OUTPUT ;
    USE SIGNAL ;
    PORT
      LAYER M5 ;
        RECT  5.856 21.408 5.88 21.6 ;
    END
  END o0[8]
  PIN o0[90]
    DIRECTION OUTPUT ;
    USE SIGNAL ;
    PORT
      LAYER M5 ;
        RECT  19.68 21.408 19.704 21.6 ;
    END
  END o0[90]
  PIN o0[91]
    DIRECTION OUTPUT ;
    USE SIGNAL ;
    PORT
      LAYER M5 ;
        RECT  19.824 21.408 19.848 21.6 ;
    END
  END o0[91]
  PIN o0[92]
    DIRECTION OUTPUT ;
    USE SIGNAL ;
    PORT
      LAYER M5 ;
        RECT  19.968 21.408 19.992 21.6 ;
    END
  END o0[92]
  PIN o0[93]
    DIRECTION OUTPUT ;
    USE SIGNAL ;
    PORT
      LAYER M5 ;
        RECT  20.16 21.408 20.184 21.6 ;
    END
  END o0[93]
  PIN o0[94]
    DIRECTION OUTPUT ;
    USE SIGNAL ;
    PORT
      LAYER M5 ;
        RECT  20.304 21.408 20.328 21.6 ;
    END
  END o0[94]
  PIN o0[95]
    DIRECTION OUTPUT ;
    USE SIGNAL ;
    PORT
      LAYER M5 ;
        RECT  20.496 21.408 20.52 21.6 ;
    END
  END o0[95]
  PIN o0[96]
    DIRECTION OUTPUT ;
    USE SIGNAL ;
    PORT
      LAYER M5 ;
        RECT  20.64 21.408 20.664 21.6 ;
    END
  END o0[96]
  PIN o0[97]
    DIRECTION OUTPUT ;
    USE SIGNAL ;
    PORT
      LAYER M5 ;
        RECT  20.832 21.408 20.856 21.6 ;
    END
  END o0[97]
  PIN o0[98]
    DIRECTION OUTPUT ;
    USE SIGNAL ;
    PORT
      LAYER M5 ;
        RECT  20.976 21.408 21 21.6 ;
    END
  END o0[98]
  PIN o0[99]
    DIRECTION OUTPUT ;
    USE SIGNAL ;
    PORT
      LAYER M5 ;
        RECT  21.168 21.408 21.192 21.6 ;
    END
  END o0[99]
  PIN o0[9]
    DIRECTION OUTPUT ;
    USE SIGNAL ;
    PORT
      LAYER M5 ;
        RECT  6 21.408 6.024 21.6 ;
    END
  END o0[9]
  PIN o1[0]
    DIRECTION OUTPUT ;
    USE SIGNAL ;
    PORT
      LAYER M5 ;
        RECT  27.552 21.408 27.576 21.6 ;
    END
  END o1[0]
  PIN o1[100]
    DIRECTION OUTPUT ;
    USE SIGNAL ;
    PORT
      LAYER M5 ;
        RECT  44.352 21.408 44.376 21.6 ;
    END
  END o1[100]
  PIN o1[101]
    DIRECTION OUTPUT ;
    USE SIGNAL ;
    PORT
      LAYER M5 ;
        RECT  44.544 21.408 44.568 21.6 ;
    END
  END o1[101]
  PIN o1[102]
    DIRECTION OUTPUT ;
    USE SIGNAL ;
    PORT
      LAYER M5 ;
        RECT  44.688 21.408 44.712 21.6 ;
    END
  END o1[102]
  PIN o1[103]
    DIRECTION OUTPUT ;
    USE SIGNAL ;
    PORT
      LAYER M5 ;
        RECT  44.88 21.408 44.904 21.6 ;
    END
  END o1[103]
  PIN o1[104]
    DIRECTION OUTPUT ;
    USE SIGNAL ;
    PORT
      LAYER M5 ;
        RECT  45.024 21.408 45.048 21.6 ;
    END
  END o1[104]
  PIN o1[105]
    DIRECTION OUTPUT ;
    USE SIGNAL ;
    PORT
      LAYER M5 ;
        RECT  45.216 21.408 45.24 21.6 ;
    END
  END o1[105]
  PIN o1[106]
    DIRECTION OUTPUT ;
    USE SIGNAL ;
    PORT
      LAYER M5 ;
        RECT  45.36 21.408 45.384 21.6 ;
    END
  END o1[106]
  PIN o1[107]
    DIRECTION OUTPUT ;
    USE SIGNAL ;
    PORT
      LAYER M5 ;
        RECT  45.504 21.408 45.528 21.6 ;
    END
  END o1[107]
  PIN o1[108]
    DIRECTION OUTPUT ;
    USE SIGNAL ;
    PORT
      LAYER M5 ;
        RECT  45.696 21.408 45.72 21.6 ;
    END
  END o1[108]
  PIN o1[109]
    DIRECTION OUTPUT ;
    USE SIGNAL ;
    PORT
      LAYER M5 ;
        RECT  45.84 21.408 45.864 21.6 ;
    END
  END o1[109]
  PIN o1[10]
    DIRECTION OUTPUT ;
    USE SIGNAL ;
    PORT
      LAYER M5 ;
        RECT  29.232 21.408 29.256 21.6 ;
    END
  END o1[10]
  PIN o1[110]
    DIRECTION OUTPUT ;
    USE SIGNAL ;
    PORT
      LAYER M5 ;
        RECT  46.032 21.408 46.056 21.6 ;
    END
  END o1[110]
  PIN o1[111]
    DIRECTION OUTPUT ;
    USE SIGNAL ;
    PORT
      LAYER M5 ;
        RECT  46.176 21.408 46.2 21.6 ;
    END
  END o1[111]
  PIN o1[112]
    DIRECTION OUTPUT ;
    USE SIGNAL ;
    PORT
      LAYER M5 ;
        RECT  46.368 21.408 46.392 21.6 ;
    END
  END o1[112]
  PIN o1[113]
    DIRECTION OUTPUT ;
    USE SIGNAL ;
    PORT
      LAYER M5 ;
        RECT  46.512 21.408 46.536 21.6 ;
    END
  END o1[113]
  PIN o1[114]
    DIRECTION OUTPUT ;
    USE SIGNAL ;
    PORT
      LAYER M5 ;
        RECT  46.704 21.408 46.728 21.6 ;
    END
  END o1[114]
  PIN o1[115]
    DIRECTION OUTPUT ;
    USE SIGNAL ;
    PORT
      LAYER M5 ;
        RECT  46.848 21.408 46.872 21.6 ;
    END
  END o1[115]
  PIN o1[116]
    DIRECTION OUTPUT ;
    USE SIGNAL ;
    PORT
      LAYER M5 ;
        RECT  47.04 21.408 47.064 21.6 ;
    END
  END o1[116]
  PIN o1[117]
    DIRECTION OUTPUT ;
    USE SIGNAL ;
    PORT
      LAYER M5 ;
        RECT  47.184 21.408 47.208 21.6 ;
    END
  END o1[117]
  PIN o1[118]
    DIRECTION OUTPUT ;
    USE SIGNAL ;
    PORT
      LAYER M5 ;
        RECT  47.376 21.408 47.4 21.6 ;
    END
  END o1[118]
  PIN o1[119]
    DIRECTION OUTPUT ;
    USE SIGNAL ;
    PORT
      LAYER M5 ;
        RECT  47.52 21.408 47.544 21.6 ;
    END
  END o1[119]
  PIN o1[11]
    DIRECTION OUTPUT ;
    USE SIGNAL ;
    PORT
      LAYER M5 ;
        RECT  29.376 21.408 29.4 21.6 ;
    END
  END o1[11]
  PIN o1[120]
    DIRECTION OUTPUT ;
    USE SIGNAL ;
    PORT
      LAYER M5 ;
        RECT  47.712 21.408 47.736 21.6 ;
    END
  END o1[120]
  PIN o1[121]
    DIRECTION OUTPUT ;
    USE SIGNAL ;
    PORT
      LAYER M5 ;
        RECT  47.856 21.408 47.88 21.6 ;
    END
  END o1[121]
  PIN o1[122]
    DIRECTION OUTPUT ;
    USE SIGNAL ;
    PORT
      LAYER M5 ;
        RECT  48 21.408 48.024 21.6 ;
    END
  END o1[122]
  PIN o1[123]
    DIRECTION OUTPUT ;
    USE SIGNAL ;
    PORT
      LAYER M5 ;
        RECT  48.192 21.408 48.216 21.6 ;
    END
  END o1[123]
  PIN o1[124]
    DIRECTION OUTPUT ;
    USE SIGNAL ;
    PORT
      LAYER M5 ;
        RECT  48.336 21.408 48.36 21.6 ;
    END
  END o1[124]
  PIN o1[125]
    DIRECTION OUTPUT ;
    USE SIGNAL ;
    PORT
      LAYER M5 ;
        RECT  48.528 21.408 48.552 21.6 ;
    END
  END o1[125]
  PIN o1[126]
    DIRECTION OUTPUT ;
    USE SIGNAL ;
    PORT
      LAYER M5 ;
        RECT  48.672 21.408 48.696 21.6 ;
    END
  END o1[126]
  PIN o1[127]
    DIRECTION OUTPUT ;
    USE SIGNAL ;
    PORT
      LAYER M5 ;
        RECT  48.864 21.408 48.888 21.6 ;
    END
  END o1[127]
  PIN o1[128]
    DIRECTION OUTPUT ;
    USE SIGNAL ;
    PORT
      LAYER M5 ;
        RECT  49.008 21.408 49.032 21.6 ;
    END
  END o1[128]
  PIN o1[129]
    DIRECTION OUTPUT ;
    USE SIGNAL ;
    PORT
      LAYER M5 ;
        RECT  49.2 21.408 49.224 21.6 ;
    END
  END o1[129]
  PIN o1[12]
    DIRECTION OUTPUT ;
    USE SIGNAL ;
    PORT
      LAYER M5 ;
        RECT  29.568 21.408 29.592 21.6 ;
    END
  END o1[12]
  PIN o1[130]
    DIRECTION OUTPUT ;
    USE SIGNAL ;
    PORT
      LAYER M5 ;
        RECT  49.344 21.408 49.368 21.6 ;
    END
  END o1[130]
  PIN o1[131]
    DIRECTION OUTPUT ;
    USE SIGNAL ;
    PORT
      LAYER M5 ;
        RECT  49.536 21.408 49.56 21.6 ;
    END
  END o1[131]
  PIN o1[132]
    DIRECTION OUTPUT ;
    USE SIGNAL ;
    PORT
      LAYER M5 ;
        RECT  49.68 21.408 49.704 21.6 ;
    END
  END o1[132]
  PIN o1[133]
    DIRECTION OUTPUT ;
    USE SIGNAL ;
    PORT
      LAYER M5 ;
        RECT  49.872 21.408 49.896 21.6 ;
    END
  END o1[133]
  PIN o1[134]
    DIRECTION OUTPUT ;
    USE SIGNAL ;
    PORT
      LAYER M5 ;
        RECT  50.016 21.408 50.04 21.6 ;
    END
  END o1[134]
  PIN o1[135]
    DIRECTION OUTPUT ;
    USE SIGNAL ;
    PORT
      LAYER M5 ;
        RECT  50.208 21.408 50.232 21.6 ;
    END
  END o1[135]
  PIN o1[13]
    DIRECTION OUTPUT ;
    USE SIGNAL ;
    PORT
      LAYER M5 ;
        RECT  29.712 21.408 29.736 21.6 ;
    END
  END o1[13]
  PIN o1[14]
    DIRECTION OUTPUT ;
    USE SIGNAL ;
    PORT
      LAYER M5 ;
        RECT  29.856 21.408 29.88 21.6 ;
    END
  END o1[14]
  PIN o1[15]
    DIRECTION OUTPUT ;
    USE SIGNAL ;
    PORT
      LAYER M5 ;
        RECT  30.048 21.408 30.072 21.6 ;
    END
  END o1[15]
  PIN o1[16]
    DIRECTION OUTPUT ;
    USE SIGNAL ;
    PORT
      LAYER M5 ;
        RECT  30.192 21.408 30.216 21.6 ;
    END
  END o1[16]
  PIN o1[17]
    DIRECTION OUTPUT ;
    USE SIGNAL ;
    PORT
      LAYER M5 ;
        RECT  30.384 21.408 30.408 21.6 ;
    END
  END o1[17]
  PIN o1[18]
    DIRECTION OUTPUT ;
    USE SIGNAL ;
    PORT
      LAYER M5 ;
        RECT  30.528 21.408 30.552 21.6 ;
    END
  END o1[18]
  PIN o1[19]
    DIRECTION OUTPUT ;
    USE SIGNAL ;
    PORT
      LAYER M5 ;
        RECT  30.72 21.408 30.744 21.6 ;
    END
  END o1[19]
  PIN o1[1]
    DIRECTION OUTPUT ;
    USE SIGNAL ;
    PORT
      LAYER M5 ;
        RECT  27.696 21.408 27.72 21.6 ;
    END
  END o1[1]
  PIN o1[20]
    DIRECTION OUTPUT ;
    USE SIGNAL ;
    PORT
      LAYER M5 ;
        RECT  30.864 21.408 30.888 21.6 ;
    END
  END o1[20]
  PIN o1[21]
    DIRECTION OUTPUT ;
    USE SIGNAL ;
    PORT
      LAYER M5 ;
        RECT  31.056 21.408 31.08 21.6 ;
    END
  END o1[21]
  PIN o1[22]
    DIRECTION OUTPUT ;
    USE SIGNAL ;
    PORT
      LAYER M5 ;
        RECT  31.2 21.408 31.224 21.6 ;
    END
  END o1[22]
  PIN o1[23]
    DIRECTION OUTPUT ;
    USE SIGNAL ;
    PORT
      LAYER M5 ;
        RECT  31.392 21.408 31.416 21.6 ;
    END
  END o1[23]
  PIN o1[24]
    DIRECTION OUTPUT ;
    USE SIGNAL ;
    PORT
      LAYER M5 ;
        RECT  31.536 21.408 31.56 21.6 ;
    END
  END o1[24]
  PIN o1[25]
    DIRECTION OUTPUT ;
    USE SIGNAL ;
    PORT
      LAYER M5 ;
        RECT  31.728 21.408 31.752 21.6 ;
    END
  END o1[25]
  PIN o1[26]
    DIRECTION OUTPUT ;
    USE SIGNAL ;
    PORT
      LAYER M5 ;
        RECT  31.872 21.408 31.896 21.6 ;
    END
  END o1[26]
  PIN o1[27]
    DIRECTION OUTPUT ;
    USE SIGNAL ;
    PORT
      LAYER M5 ;
        RECT  32.064 21.408 32.088 21.6 ;
    END
  END o1[27]
  PIN o1[28]
    DIRECTION OUTPUT ;
    USE SIGNAL ;
    PORT
      LAYER M5 ;
        RECT  32.208 21.408 32.232 21.6 ;
    END
  END o1[28]
  PIN o1[29]
    DIRECTION OUTPUT ;
    USE SIGNAL ;
    PORT
      LAYER M5 ;
        RECT  32.352 21.408 32.376 21.6 ;
    END
  END o1[29]
  PIN o1[2]
    DIRECTION OUTPUT ;
    USE SIGNAL ;
    PORT
      LAYER M5 ;
        RECT  27.888 21.408 27.912 21.6 ;
    END
  END o1[2]
  PIN o1[30]
    DIRECTION OUTPUT ;
    USE SIGNAL ;
    PORT
      LAYER M5 ;
        RECT  32.544 21.408 32.568 21.6 ;
    END
  END o1[30]
  PIN o1[31]
    DIRECTION OUTPUT ;
    USE SIGNAL ;
    PORT
      LAYER M5 ;
        RECT  32.688 21.408 32.712 21.6 ;
    END
  END o1[31]
  PIN o1[32]
    DIRECTION OUTPUT ;
    USE SIGNAL ;
    PORT
      LAYER M5 ;
        RECT  32.88 21.408 32.904 21.6 ;
    END
  END o1[32]
  PIN o1[33]
    DIRECTION OUTPUT ;
    USE SIGNAL ;
    PORT
      LAYER M5 ;
        RECT  33.024 21.408 33.048 21.6 ;
    END
  END o1[33]
  PIN o1[34]
    DIRECTION OUTPUT ;
    USE SIGNAL ;
    PORT
      LAYER M5 ;
        RECT  33.216 21.408 33.24 21.6 ;
    END
  END o1[34]
  PIN o1[35]
    DIRECTION OUTPUT ;
    USE SIGNAL ;
    PORT
      LAYER M5 ;
        RECT  33.36 21.408 33.384 21.6 ;
    END
  END o1[35]
  PIN o1[36]
    DIRECTION OUTPUT ;
    USE SIGNAL ;
    PORT
      LAYER M5 ;
        RECT  33.552 21.408 33.576 21.6 ;
    END
  END o1[36]
  PIN o1[37]
    DIRECTION OUTPUT ;
    USE SIGNAL ;
    PORT
      LAYER M5 ;
        RECT  33.696 21.408 33.72 21.6 ;
    END
  END o1[37]
  PIN o1[38]
    DIRECTION OUTPUT ;
    USE SIGNAL ;
    PORT
      LAYER M5 ;
        RECT  33.888 21.408 33.912 21.6 ;
    END
  END o1[38]
  PIN o1[39]
    DIRECTION OUTPUT ;
    USE SIGNAL ;
    PORT
      LAYER M5 ;
        RECT  34.032 21.408 34.056 21.6 ;
    END
  END o1[39]
  PIN o1[3]
    DIRECTION OUTPUT ;
    USE SIGNAL ;
    PORT
      LAYER M5 ;
        RECT  28.032 21.408 28.056 21.6 ;
    END
  END o1[3]
  PIN o1[40]
    DIRECTION OUTPUT ;
    USE SIGNAL ;
    PORT
      LAYER M5 ;
        RECT  34.224 21.408 34.248 21.6 ;
    END
  END o1[40]
  PIN o1[41]
    DIRECTION OUTPUT ;
    USE SIGNAL ;
    PORT
      LAYER M5 ;
        RECT  34.368 21.408 34.392 21.6 ;
    END
  END o1[41]
  PIN o1[42]
    DIRECTION OUTPUT ;
    USE SIGNAL ;
    PORT
      LAYER M5 ;
        RECT  34.56 21.408 34.584 21.6 ;
    END
  END o1[42]
  PIN o1[43]
    DIRECTION OUTPUT ;
    USE SIGNAL ;
    PORT
      LAYER M5 ;
        RECT  34.704 21.408 34.728 21.6 ;
    END
  END o1[43]
  PIN o1[44]
    DIRECTION OUTPUT ;
    USE SIGNAL ;
    PORT
      LAYER M5 ;
        RECT  34.896 21.408 34.92 21.6 ;
    END
  END o1[44]
  PIN o1[45]
    DIRECTION OUTPUT ;
    USE SIGNAL ;
    PORT
      LAYER M5 ;
        RECT  35.04 21.408 35.064 21.6 ;
    END
  END o1[45]
  PIN o1[46]
    DIRECTION OUTPUT ;
    USE SIGNAL ;
    PORT
      LAYER M5 ;
        RECT  35.184 21.408 35.208 21.6 ;
    END
  END o1[46]
  PIN o1[47]
    DIRECTION OUTPUT ;
    USE SIGNAL ;
    PORT
      LAYER M5 ;
        RECT  35.376 21.408 35.4 21.6 ;
    END
  END o1[47]
  PIN o1[48]
    DIRECTION OUTPUT ;
    USE SIGNAL ;
    PORT
      LAYER M5 ;
        RECT  35.52 21.408 35.544 21.6 ;
    END
  END o1[48]
  PIN o1[49]
    DIRECTION OUTPUT ;
    USE SIGNAL ;
    PORT
      LAYER M5 ;
        RECT  35.712 21.408 35.736 21.6 ;
    END
  END o1[49]
  PIN o1[4]
    DIRECTION OUTPUT ;
    USE SIGNAL ;
    PORT
      LAYER M5 ;
        RECT  28.224 21.408 28.248 21.6 ;
    END
  END o1[4]
  PIN o1[50]
    DIRECTION OUTPUT ;
    USE SIGNAL ;
    PORT
      LAYER M5 ;
        RECT  35.856 21.408 35.88 21.6 ;
    END
  END o1[50]
  PIN o1[51]
    DIRECTION OUTPUT ;
    USE SIGNAL ;
    PORT
      LAYER M5 ;
        RECT  36.048 21.408 36.072 21.6 ;
    END
  END o1[51]
  PIN o1[52]
    DIRECTION OUTPUT ;
    USE SIGNAL ;
    PORT
      LAYER M5 ;
        RECT  36.192 21.408 36.216 21.6 ;
    END
  END o1[52]
  PIN o1[53]
    DIRECTION OUTPUT ;
    USE SIGNAL ;
    PORT
      LAYER M5 ;
        RECT  36.384 21.408 36.408 21.6 ;
    END
  END o1[53]
  PIN o1[54]
    DIRECTION OUTPUT ;
    USE SIGNAL ;
    PORT
      LAYER M5 ;
        RECT  36.528 21.408 36.552 21.6 ;
    END
  END o1[54]
  PIN o1[55]
    DIRECTION OUTPUT ;
    USE SIGNAL ;
    PORT
      LAYER M5 ;
        RECT  36.72 21.408 36.744 21.6 ;
    END
  END o1[55]
  PIN o1[56]
    DIRECTION OUTPUT ;
    USE SIGNAL ;
    PORT
      LAYER M5 ;
        RECT  36.864 21.408 36.888 21.6 ;
    END
  END o1[56]
  PIN o1[57]
    DIRECTION OUTPUT ;
    USE SIGNAL ;
    PORT
      LAYER M5 ;
        RECT  37.056 21.408 37.08 21.6 ;
    END
  END o1[57]
  PIN o1[58]
    DIRECTION OUTPUT ;
    USE SIGNAL ;
    PORT
      LAYER M5 ;
        RECT  37.2 21.408 37.224 21.6 ;
    END
  END o1[58]
  PIN o1[59]
    DIRECTION OUTPUT ;
    USE SIGNAL ;
    PORT
      LAYER M5 ;
        RECT  37.392 21.408 37.416 21.6 ;
    END
  END o1[59]
  PIN o1[5]
    DIRECTION OUTPUT ;
    USE SIGNAL ;
    PORT
      LAYER M5 ;
        RECT  28.368 21.408 28.392 21.6 ;
    END
  END o1[5]
  PIN o1[60]
    DIRECTION OUTPUT ;
    USE SIGNAL ;
    PORT
      LAYER M5 ;
        RECT  37.536 21.408 37.56 21.6 ;
    END
  END o1[60]
  PIN o1[61]
    DIRECTION OUTPUT ;
    USE SIGNAL ;
    PORT
      LAYER M5 ;
        RECT  37.68 21.408 37.704 21.6 ;
    END
  END o1[61]
  PIN o1[62]
    DIRECTION OUTPUT ;
    USE SIGNAL ;
    PORT
      LAYER M5 ;
        RECT  37.872 21.408 37.896 21.6 ;
    END
  END o1[62]
  PIN o1[63]
    DIRECTION OUTPUT ;
    USE SIGNAL ;
    PORT
      LAYER M5 ;
        RECT  38.016 21.408 38.04 21.6 ;
    END
  END o1[63]
  PIN o1[64]
    DIRECTION OUTPUT ;
    USE SIGNAL ;
    PORT
      LAYER M5 ;
        RECT  38.208 21.408 38.232 21.6 ;
    END
  END o1[64]
  PIN o1[65]
    DIRECTION OUTPUT ;
    USE SIGNAL ;
    PORT
      LAYER M5 ;
        RECT  38.352 21.408 38.376 21.6 ;
    END
  END o1[65]
  PIN o1[66]
    DIRECTION OUTPUT ;
    USE SIGNAL ;
    PORT
      LAYER M5 ;
        RECT  38.544 21.408 38.568 21.6 ;
    END
  END o1[66]
  PIN o1[67]
    DIRECTION OUTPUT ;
    USE SIGNAL ;
    PORT
      LAYER M5 ;
        RECT  38.688 21.408 38.712 21.6 ;
    END
  END o1[67]
  PIN o1[68]
    DIRECTION OUTPUT ;
    USE SIGNAL ;
    PORT
      LAYER M5 ;
        RECT  39.024 21.408 39.048 21.6 ;
    END
  END o1[68]
  PIN o1[69]
    DIRECTION OUTPUT ;
    USE SIGNAL ;
    PORT
      LAYER M5 ;
        RECT  39.216 21.408 39.24 21.6 ;
    END
  END o1[69]
  PIN o1[6]
    DIRECTION OUTPUT ;
    USE SIGNAL ;
    PORT
      LAYER M5 ;
        RECT  28.56 21.408 28.584 21.6 ;
    END
  END o1[6]
  PIN o1[70]
    DIRECTION OUTPUT ;
    USE SIGNAL ;
    PORT
      LAYER M5 ;
        RECT  39.36 21.408 39.384 21.6 ;
    END
  END o1[70]
  PIN o1[71]
    DIRECTION OUTPUT ;
    USE SIGNAL ;
    PORT
      LAYER M5 ;
        RECT  39.552 21.408 39.576 21.6 ;
    END
  END o1[71]
  PIN o1[72]
    DIRECTION OUTPUT ;
    USE SIGNAL ;
    PORT
      LAYER M5 ;
        RECT  39.696 21.408 39.72 21.6 ;
    END
  END o1[72]
  PIN o1[73]
    DIRECTION OUTPUT ;
    USE SIGNAL ;
    PORT
      LAYER M5 ;
        RECT  39.888 21.408 39.912 21.6 ;
    END
  END o1[73]
  PIN o1[74]
    DIRECTION OUTPUT ;
    USE SIGNAL ;
    PORT
      LAYER M5 ;
        RECT  40.032 21.408 40.056 21.6 ;
    END
  END o1[74]
  PIN o1[75]
    DIRECTION OUTPUT ;
    USE SIGNAL ;
    PORT
      LAYER M5 ;
        RECT  40.176 21.408 40.2 21.6 ;
    END
  END o1[75]
  PIN o1[76]
    DIRECTION OUTPUT ;
    USE SIGNAL ;
    PORT
      LAYER M5 ;
        RECT  40.368 21.408 40.392 21.6 ;
    END
  END o1[76]
  PIN o1[77]
    DIRECTION OUTPUT ;
    USE SIGNAL ;
    PORT
      LAYER M5 ;
        RECT  40.512 21.408 40.536 21.6 ;
    END
  END o1[77]
  PIN o1[78]
    DIRECTION OUTPUT ;
    USE SIGNAL ;
    PORT
      LAYER M5 ;
        RECT  40.704 21.408 40.728 21.6 ;
    END
  END o1[78]
  PIN o1[79]
    DIRECTION OUTPUT ;
    USE SIGNAL ;
    PORT
      LAYER M5 ;
        RECT  40.848 21.408 40.872 21.6 ;
    END
  END o1[79]
  PIN o1[7]
    DIRECTION OUTPUT ;
    USE SIGNAL ;
    PORT
      LAYER M5 ;
        RECT  28.704 21.408 28.728 21.6 ;
    END
  END o1[7]
  PIN o1[80]
    DIRECTION OUTPUT ;
    USE SIGNAL ;
    PORT
      LAYER M5 ;
        RECT  41.04 21.408 41.064 21.6 ;
    END
  END o1[80]
  PIN o1[81]
    DIRECTION OUTPUT ;
    USE SIGNAL ;
    PORT
      LAYER M5 ;
        RECT  41.184 21.408 41.208 21.6 ;
    END
  END o1[81]
  PIN o1[82]
    DIRECTION OUTPUT ;
    USE SIGNAL ;
    PORT
      LAYER M5 ;
        RECT  41.376 21.408 41.4 21.6 ;
    END
  END o1[82]
  PIN o1[83]
    DIRECTION OUTPUT ;
    USE SIGNAL ;
    PORT
      LAYER M5 ;
        RECT  41.52 21.408 41.544 21.6 ;
    END
  END o1[83]
  PIN o1[84]
    DIRECTION OUTPUT ;
    USE SIGNAL ;
    PORT
      LAYER M5 ;
        RECT  41.712 21.408 41.736 21.6 ;
    END
  END o1[84]
  PIN o1[85]
    DIRECTION OUTPUT ;
    USE SIGNAL ;
    PORT
      LAYER M5 ;
        RECT  41.856 21.408 41.88 21.6 ;
    END
  END o1[85]
  PIN o1[86]
    DIRECTION OUTPUT ;
    USE SIGNAL ;
    PORT
      LAYER M5 ;
        RECT  42.048 21.408 42.072 21.6 ;
    END
  END o1[86]
  PIN o1[87]
    DIRECTION OUTPUT ;
    USE SIGNAL ;
    PORT
      LAYER M5 ;
        RECT  42.192 21.408 42.216 21.6 ;
    END
  END o1[87]
  PIN o1[88]
    DIRECTION OUTPUT ;
    USE SIGNAL ;
    PORT
      LAYER M5 ;
        RECT  42.384 21.408 42.408 21.6 ;
    END
  END o1[88]
  PIN o1[89]
    DIRECTION OUTPUT ;
    USE SIGNAL ;
    PORT
      LAYER M5 ;
        RECT  42.528 21.408 42.552 21.6 ;
    END
  END o1[89]
  PIN o1[8]
    DIRECTION OUTPUT ;
    USE SIGNAL ;
    PORT
      LAYER M5 ;
        RECT  28.896 21.408 28.92 21.6 ;
    END
  END o1[8]
  PIN o1[90]
    DIRECTION OUTPUT ;
    USE SIGNAL ;
    PORT
      LAYER M5 ;
        RECT  42.72 21.408 42.744 21.6 ;
    END
  END o1[90]
  PIN o1[91]
    DIRECTION OUTPUT ;
    USE SIGNAL ;
    PORT
      LAYER M5 ;
        RECT  42.864 21.408 42.888 21.6 ;
    END
  END o1[91]
  PIN o1[92]
    DIRECTION OUTPUT ;
    USE SIGNAL ;
    PORT
      LAYER M5 ;
        RECT  43.008 21.408 43.032 21.6 ;
    END
  END o1[92]
  PIN o1[93]
    DIRECTION OUTPUT ;
    USE SIGNAL ;
    PORT
      LAYER M5 ;
        RECT  43.2 21.408 43.224 21.6 ;
    END
  END o1[93]
  PIN o1[94]
    DIRECTION OUTPUT ;
    USE SIGNAL ;
    PORT
      LAYER M5 ;
        RECT  43.344 21.408 43.368 21.6 ;
    END
  END o1[94]
  PIN o1[95]
    DIRECTION OUTPUT ;
    USE SIGNAL ;
    PORT
      LAYER M5 ;
        RECT  43.536 21.408 43.56 21.6 ;
    END
  END o1[95]
  PIN o1[96]
    DIRECTION OUTPUT ;
    USE SIGNAL ;
    PORT
      LAYER M5 ;
        RECT  43.68 21.408 43.704 21.6 ;
    END
  END o1[96]
  PIN o1[97]
    DIRECTION OUTPUT ;
    USE SIGNAL ;
    PORT
      LAYER M5 ;
        RECT  43.872 21.408 43.896 21.6 ;
    END
  END o1[97]
  PIN o1[98]
    DIRECTION OUTPUT ;
    USE SIGNAL ;
    PORT
      LAYER M5 ;
        RECT  44.016 21.408 44.04 21.6 ;
    END
  END o1[98]
  PIN o1[99]
    DIRECTION OUTPUT ;
    USE SIGNAL ;
    PORT
      LAYER M5 ;
        RECT  44.208 21.408 44.232 21.6 ;
    END
  END o1[99]
  PIN o1[9]
    DIRECTION OUTPUT ;
    USE SIGNAL ;
    PORT
      LAYER M5 ;
        RECT  29.04 21.408 29.064 21.6 ;
    END
  END o1[9]
  PIN o2[0]
    DIRECTION OUTPUT ;
    USE SIGNAL ;
    PORT
      LAYER M5 ;
        RECT  39.072 0 39.096 0.192 ;
    END
  END o2[0]
  PIN o2[100]
    DIRECTION OUTPUT ;
    USE SIGNAL ;
    PORT
      LAYER M5 ;
        RECT  64.416 0 64.44 0.192 ;
    END
  END o2[100]
  PIN o2[101]
    DIRECTION OUTPUT ;
    USE SIGNAL ;
    PORT
      LAYER M5 ;
        RECT  64.704 0 64.728 0.192 ;
    END
  END o2[101]
  PIN o2[102]
    DIRECTION OUTPUT ;
    USE SIGNAL ;
    PORT
      LAYER M5 ;
        RECT  64.944 0 64.968 0.192 ;
    END
  END o2[102]
  PIN o2[103]
    DIRECTION OUTPUT ;
    USE SIGNAL ;
    PORT
      LAYER M5 ;
        RECT  65.184 0 65.208 0.192 ;
    END
  END o2[103]
  PIN o2[104]
    DIRECTION OUTPUT ;
    USE SIGNAL ;
    PORT
      LAYER M5 ;
        RECT  65.424 0 65.448 0.192 ;
    END
  END o2[104]
  PIN o2[105]
    DIRECTION OUTPUT ;
    USE SIGNAL ;
    PORT
      LAYER M5 ;
        RECT  65.712 0 65.736 0.192 ;
    END
  END o2[105]
  PIN o2[106]
    DIRECTION OUTPUT ;
    USE SIGNAL ;
    PORT
      LAYER M5 ;
        RECT  65.952 0 65.976 0.192 ;
    END
  END o2[106]
  PIN o2[107]
    DIRECTION OUTPUT ;
    USE SIGNAL ;
    PORT
      LAYER M5 ;
        RECT  66.192 0 66.216 0.192 ;
    END
  END o2[107]
  PIN o2[108]
    DIRECTION OUTPUT ;
    USE SIGNAL ;
    PORT
      LAYER M5 ;
        RECT  66.432 0 66.456 0.192 ;
    END
  END o2[108]
  PIN o2[109]
    DIRECTION OUTPUT ;
    USE SIGNAL ;
    PORT
      LAYER M5 ;
        RECT  66.72 0 66.744 0.192 ;
    END
  END o2[109]
  PIN o2[10]
    DIRECTION OUTPUT ;
    USE SIGNAL ;
    PORT
      LAYER M5 ;
        RECT  41.568 0 41.592 0.192 ;
    END
  END o2[10]
  PIN o2[110]
    DIRECTION OUTPUT ;
    USE SIGNAL ;
    PORT
      LAYER M5 ;
        RECT  66.96 0 66.984 0.192 ;
    END
  END o2[110]
  PIN o2[111]
    DIRECTION OUTPUT ;
    USE SIGNAL ;
    PORT
      LAYER M5 ;
        RECT  67.2 0 67.224 0.192 ;
    END
  END o2[111]
  PIN o2[112]
    DIRECTION OUTPUT ;
    USE SIGNAL ;
    PORT
      LAYER M5 ;
        RECT  67.44 0 67.464 0.192 ;
    END
  END o2[112]
  PIN o2[113]
    DIRECTION OUTPUT ;
    USE SIGNAL ;
    PORT
      LAYER M5 ;
        RECT  67.68 0 67.704 0.192 ;
    END
  END o2[113]
  PIN o2[114]
    DIRECTION OUTPUT ;
    USE SIGNAL ;
    PORT
      LAYER M5 ;
        RECT  67.968 0 67.992 0.192 ;
    END
  END o2[114]
  PIN o2[115]
    DIRECTION OUTPUT ;
    USE SIGNAL ;
    PORT
      LAYER M5 ;
        RECT  68.208 0 68.232 0.192 ;
    END
  END o2[115]
  PIN o2[116]
    DIRECTION OUTPUT ;
    USE SIGNAL ;
    PORT
      LAYER M5 ;
        RECT  68.448 0 68.472 0.192 ;
    END
  END o2[116]
  PIN o2[117]
    DIRECTION OUTPUT ;
    USE SIGNAL ;
    PORT
      LAYER M5 ;
        RECT  68.688 0 68.712 0.192 ;
    END
  END o2[117]
  PIN o2[118]
    DIRECTION OUTPUT ;
    USE SIGNAL ;
    PORT
      LAYER M5 ;
        RECT  68.976 0 69 0.192 ;
    END
  END o2[118]
  PIN o2[119]
    DIRECTION OUTPUT ;
    USE SIGNAL ;
    PORT
      LAYER M5 ;
        RECT  69.216 0 69.24 0.192 ;
    END
  END o2[119]
  PIN o2[11]
    DIRECTION OUTPUT ;
    USE SIGNAL ;
    PORT
      LAYER M5 ;
        RECT  41.808 0 41.832 0.192 ;
    END
  END o2[11]
  PIN o2[120]
    DIRECTION OUTPUT ;
    USE SIGNAL ;
    PORT
      LAYER M5 ;
        RECT  69.456 0 69.48 0.192 ;
    END
  END o2[120]
  PIN o2[121]
    DIRECTION OUTPUT ;
    USE SIGNAL ;
    PORT
      LAYER M5 ;
        RECT  69.696 0 69.72 0.192 ;
    END
  END o2[121]
  PIN o2[122]
    DIRECTION OUTPUT ;
    USE SIGNAL ;
    PORT
      LAYER M5 ;
        RECT  69.984 0 70.008 0.192 ;
    END
  END o2[122]
  PIN o2[123]
    DIRECTION OUTPUT ;
    USE SIGNAL ;
    PORT
      LAYER M5 ;
        RECT  70.224 0 70.248 0.192 ;
    END
  END o2[123]
  PIN o2[124]
    DIRECTION OUTPUT ;
    USE SIGNAL ;
    PORT
      LAYER M5 ;
        RECT  70.464 0 70.488 0.192 ;
    END
  END o2[124]
  PIN o2[125]
    DIRECTION OUTPUT ;
    USE SIGNAL ;
    PORT
      LAYER M5 ;
        RECT  70.704 0 70.728 0.192 ;
    END
  END o2[125]
  PIN o2[126]
    DIRECTION OUTPUT ;
    USE SIGNAL ;
    PORT
      LAYER M5 ;
        RECT  70.944 0 70.968 0.192 ;
    END
  END o2[126]
  PIN o2[127]
    DIRECTION OUTPUT ;
    USE SIGNAL ;
    PORT
      LAYER M5 ;
        RECT  71.232 0 71.256 0.192 ;
    END
  END o2[127]
  PIN o2[128]
    DIRECTION OUTPUT ;
    USE SIGNAL ;
    PORT
      LAYER M5 ;
        RECT  71.472 0 71.496 0.192 ;
    END
  END o2[128]
  PIN o2[129]
    DIRECTION OUTPUT ;
    USE SIGNAL ;
    PORT
      LAYER M5 ;
        RECT  71.712 0 71.736 0.192 ;
    END
  END o2[129]
  PIN o2[12]
    DIRECTION OUTPUT ;
    USE SIGNAL ;
    PORT
      LAYER M5 ;
        RECT  42.096 0 42.12 0.192 ;
    END
  END o2[12]
  PIN o2[130]
    DIRECTION OUTPUT ;
    USE SIGNAL ;
    PORT
      LAYER M5 ;
        RECT  71.952 0 71.976 0.192 ;
    END
  END o2[130]
  PIN o2[131]
    DIRECTION OUTPUT ;
    USE SIGNAL ;
    PORT
      LAYER M5 ;
        RECT  72.24 0 72.264 0.192 ;
    END
  END o2[131]
  PIN o2[132]
    DIRECTION OUTPUT ;
    USE SIGNAL ;
    PORT
      LAYER M5 ;
        RECT  72.48 0 72.504 0.192 ;
    END
  END o2[132]
  PIN o2[133]
    DIRECTION OUTPUT ;
    USE SIGNAL ;
    PORT
      LAYER M5 ;
        RECT  72.72 0 72.744 0.192 ;
    END
  END o2[133]
  PIN o2[134]
    DIRECTION OUTPUT ;
    USE SIGNAL ;
    PORT
      LAYER M5 ;
        RECT  72.96 0 72.984 0.192 ;
    END
  END o2[134]
  PIN o2[135]
    DIRECTION OUTPUT ;
    USE SIGNAL ;
    PORT
      LAYER M5 ;
        RECT  73.248 0 73.272 0.192 ;
    END
  END o2[135]
  PIN o2[13]
    DIRECTION OUTPUT ;
    USE SIGNAL ;
    PORT
      LAYER M5 ;
        RECT  42.336 0 42.36 0.192 ;
    END
  END o2[13]
  PIN o2[14]
    DIRECTION OUTPUT ;
    USE SIGNAL ;
    PORT
      LAYER M5 ;
        RECT  42.576 0 42.6 0.192 ;
    END
  END o2[14]
  PIN o2[15]
    DIRECTION OUTPUT ;
    USE SIGNAL ;
    PORT
      LAYER M5 ;
        RECT  42.816 0 42.84 0.192 ;
    END
  END o2[15]
  PIN o2[16]
    DIRECTION OUTPUT ;
    USE SIGNAL ;
    PORT
      LAYER M5 ;
        RECT  43.104 0 43.128 0.192 ;
    END
  END o2[16]
  PIN o2[17]
    DIRECTION OUTPUT ;
    USE SIGNAL ;
    PORT
      LAYER M5 ;
        RECT  43.344 0 43.368 0.192 ;
    END
  END o2[17]
  PIN o2[18]
    DIRECTION OUTPUT ;
    USE SIGNAL ;
    PORT
      LAYER M5 ;
        RECT  43.584 0 43.608 0.192 ;
    END
  END o2[18]
  PIN o2[19]
    DIRECTION OUTPUT ;
    USE SIGNAL ;
    PORT
      LAYER M5 ;
        RECT  43.824 0 43.848 0.192 ;
    END
  END o2[19]
  PIN o2[1]
    DIRECTION OUTPUT ;
    USE SIGNAL ;
    PORT
      LAYER M5 ;
        RECT  39.312 0 39.336 0.192 ;
    END
  END o2[1]
  PIN o2[20]
    DIRECTION OUTPUT ;
    USE SIGNAL ;
    PORT
      LAYER M5 ;
        RECT  44.112 0 44.136 0.192 ;
    END
  END o2[20]
  PIN o2[21]
    DIRECTION OUTPUT ;
    USE SIGNAL ;
    PORT
      LAYER M5 ;
        RECT  44.352 0 44.376 0.192 ;
    END
  END o2[21]
  PIN o2[22]
    DIRECTION OUTPUT ;
    USE SIGNAL ;
    PORT
      LAYER M5 ;
        RECT  44.592 0 44.616 0.192 ;
    END
  END o2[22]
  PIN o2[23]
    DIRECTION OUTPUT ;
    USE SIGNAL ;
    PORT
      LAYER M5 ;
        RECT  44.832 0 44.856 0.192 ;
    END
  END o2[23]
  PIN o2[24]
    DIRECTION OUTPUT ;
    USE SIGNAL ;
    PORT
      LAYER M5 ;
        RECT  45.12 0 45.144 0.192 ;
    END
  END o2[24]
  PIN o2[25]
    DIRECTION OUTPUT ;
    USE SIGNAL ;
    PORT
      LAYER M5 ;
        RECT  45.36 0 45.384 0.192 ;
    END
  END o2[25]
  PIN o2[26]
    DIRECTION OUTPUT ;
    USE SIGNAL ;
    PORT
      LAYER M5 ;
        RECT  45.6 0 45.624 0.192 ;
    END
  END o2[26]
  PIN o2[27]
    DIRECTION OUTPUT ;
    USE SIGNAL ;
    PORT
      LAYER M5 ;
        RECT  45.84 0 45.864 0.192 ;
    END
  END o2[27]
  PIN o2[28]
    DIRECTION OUTPUT ;
    USE SIGNAL ;
    PORT
      LAYER M5 ;
        RECT  46.08 0 46.104 0.192 ;
    END
  END o2[28]
  PIN o2[29]
    DIRECTION OUTPUT ;
    USE SIGNAL ;
    PORT
      LAYER M5 ;
        RECT  46.368 0 46.392 0.192 ;
    END
  END o2[29]
  PIN o2[2]
    DIRECTION OUTPUT ;
    USE SIGNAL ;
    PORT
      LAYER M5 ;
        RECT  39.552 0 39.576 0.192 ;
    END
  END o2[2]
  PIN o2[30]
    DIRECTION OUTPUT ;
    USE SIGNAL ;
    PORT
      LAYER M5 ;
        RECT  46.608 0 46.632 0.192 ;
    END
  END o2[30]
  PIN o2[31]
    DIRECTION OUTPUT ;
    USE SIGNAL ;
    PORT
      LAYER M5 ;
        RECT  46.848 0 46.872 0.192 ;
    END
  END o2[31]
  PIN o2[32]
    DIRECTION OUTPUT ;
    USE SIGNAL ;
    PORT
      LAYER M5 ;
        RECT  47.088 0 47.112 0.192 ;
    END
  END o2[32]
  PIN o2[33]
    DIRECTION OUTPUT ;
    USE SIGNAL ;
    PORT
      LAYER M5 ;
        RECT  47.376 0 47.4 0.192 ;
    END
  END o2[33]
  PIN o2[34]
    DIRECTION OUTPUT ;
    USE SIGNAL ;
    PORT
      LAYER M5 ;
        RECT  47.616 0 47.64 0.192 ;
    END
  END o2[34]
  PIN o2[35]
    DIRECTION OUTPUT ;
    USE SIGNAL ;
    PORT
      LAYER M5 ;
        RECT  47.856 0 47.88 0.192 ;
    END
  END o2[35]
  PIN o2[36]
    DIRECTION OUTPUT ;
    USE SIGNAL ;
    PORT
      LAYER M5 ;
        RECT  48.096 0 48.12 0.192 ;
    END
  END o2[36]
  PIN o2[37]
    DIRECTION OUTPUT ;
    USE SIGNAL ;
    PORT
      LAYER M5 ;
        RECT  48.384 0 48.408 0.192 ;
    END
  END o2[37]
  PIN o2[38]
    DIRECTION OUTPUT ;
    USE SIGNAL ;
    PORT
      LAYER M5 ;
        RECT  48.624 0 48.648 0.192 ;
    END
  END o2[38]
  PIN o2[39]
    DIRECTION OUTPUT ;
    USE SIGNAL ;
    PORT
      LAYER M5 ;
        RECT  48.864 0 48.888 0.192 ;
    END
  END o2[39]
  PIN o2[3]
    DIRECTION OUTPUT ;
    USE SIGNAL ;
    PORT
      LAYER M5 ;
        RECT  39.84 0 39.864 0.192 ;
    END
  END o2[3]
  PIN o2[40]
    DIRECTION OUTPUT ;
    USE SIGNAL ;
    PORT
      LAYER M5 ;
        RECT  49.104 0 49.128 0.192 ;
    END
  END o2[40]
  PIN o2[41]
    DIRECTION OUTPUT ;
    USE SIGNAL ;
    PORT
      LAYER M5 ;
        RECT  49.344 0 49.368 0.192 ;
    END
  END o2[41]
  PIN o2[42]
    DIRECTION OUTPUT ;
    USE SIGNAL ;
    PORT
      LAYER M5 ;
        RECT  49.632 0 49.656 0.192 ;
    END
  END o2[42]
  PIN o2[43]
    DIRECTION OUTPUT ;
    USE SIGNAL ;
    PORT
      LAYER M5 ;
        RECT  49.872 0 49.896 0.192 ;
    END
  END o2[43]
  PIN o2[44]
    DIRECTION OUTPUT ;
    USE SIGNAL ;
    PORT
      LAYER M5 ;
        RECT  50.112 0 50.136 0.192 ;
    END
  END o2[44]
  PIN o2[45]
    DIRECTION OUTPUT ;
    USE SIGNAL ;
    PORT
      LAYER M5 ;
        RECT  50.352 0 50.376 0.192 ;
    END
  END o2[45]
  PIN o2[46]
    DIRECTION OUTPUT ;
    USE SIGNAL ;
    PORT
      LAYER M5 ;
        RECT  50.64 0 50.664 0.192 ;
    END
  END o2[46]
  PIN o2[47]
    DIRECTION OUTPUT ;
    USE SIGNAL ;
    PORT
      LAYER M5 ;
        RECT  50.88 0 50.904 0.192 ;
    END
  END o2[47]
  PIN o2[48]
    DIRECTION OUTPUT ;
    USE SIGNAL ;
    PORT
      LAYER M5 ;
        RECT  51.12 0 51.144 0.192 ;
    END
  END o2[48]
  PIN o2[49]
    DIRECTION OUTPUT ;
    USE SIGNAL ;
    PORT
      LAYER M5 ;
        RECT  51.36 0 51.384 0.192 ;
    END
  END o2[49]
  PIN o2[4]
    DIRECTION OUTPUT ;
    USE SIGNAL ;
    PORT
      LAYER M5 ;
        RECT  40.08 0 40.104 0.192 ;
    END
  END o2[4]
  PIN o2[50]
    DIRECTION OUTPUT ;
    USE SIGNAL ;
    PORT
      LAYER M5 ;
        RECT  51.648 0 51.672 0.192 ;
    END
  END o2[50]
  PIN o2[51]
    DIRECTION OUTPUT ;
    USE SIGNAL ;
    PORT
      LAYER M5 ;
        RECT  51.888 0 51.912 0.192 ;
    END
  END o2[51]
  PIN o2[52]
    DIRECTION OUTPUT ;
    USE SIGNAL ;
    PORT
      LAYER M5 ;
        RECT  52.128 0 52.152 0.192 ;
    END
  END o2[52]
  PIN o2[53]
    DIRECTION OUTPUT ;
    USE SIGNAL ;
    PORT
      LAYER M5 ;
        RECT  52.368 0 52.392 0.192 ;
    END
  END o2[53]
  PIN o2[54]
    DIRECTION OUTPUT ;
    USE SIGNAL ;
    PORT
      LAYER M5 ;
        RECT  52.608 0 52.632 0.192 ;
    END
  END o2[54]
  PIN o2[55]
    DIRECTION OUTPUT ;
    USE SIGNAL ;
    PORT
      LAYER M5 ;
        RECT  52.896 0 52.92 0.192 ;
    END
  END o2[55]
  PIN o2[56]
    DIRECTION OUTPUT ;
    USE SIGNAL ;
    PORT
      LAYER M5 ;
        RECT  53.136 0 53.16 0.192 ;
    END
  END o2[56]
  PIN o2[57]
    DIRECTION OUTPUT ;
    USE SIGNAL ;
    PORT
      LAYER M5 ;
        RECT  53.376 0 53.4 0.192 ;
    END
  END o2[57]
  PIN o2[58]
    DIRECTION OUTPUT ;
    USE SIGNAL ;
    PORT
      LAYER M5 ;
        RECT  53.616 0 53.64 0.192 ;
    END
  END o2[58]
  PIN o2[59]
    DIRECTION OUTPUT ;
    USE SIGNAL ;
    PORT
      LAYER M5 ;
        RECT  53.904 0 53.928 0.192 ;
    END
  END o2[59]
  PIN o2[5]
    DIRECTION OUTPUT ;
    USE SIGNAL ;
    PORT
      LAYER M5 ;
        RECT  40.32 0 40.344 0.192 ;
    END
  END o2[5]
  PIN o2[60]
    DIRECTION OUTPUT ;
    USE SIGNAL ;
    PORT
      LAYER M5 ;
        RECT  54.144 0 54.168 0.192 ;
    END
  END o2[60]
  PIN o2[61]
    DIRECTION OUTPUT ;
    USE SIGNAL ;
    PORT
      LAYER M5 ;
        RECT  54.384 0 54.408 0.192 ;
    END
  END o2[61]
  PIN o2[62]
    DIRECTION OUTPUT ;
    USE SIGNAL ;
    PORT
      LAYER M5 ;
        RECT  54.624 0 54.648 0.192 ;
    END
  END o2[62]
  PIN o2[63]
    DIRECTION OUTPUT ;
    USE SIGNAL ;
    PORT
      LAYER M5 ;
        RECT  54.912 0 54.936 0.192 ;
    END
  END o2[63]
  PIN o2[64]
    DIRECTION OUTPUT ;
    USE SIGNAL ;
    PORT
      LAYER M5 ;
        RECT  55.152 0 55.176 0.192 ;
    END
  END o2[64]
  PIN o2[65]
    DIRECTION OUTPUT ;
    USE SIGNAL ;
    PORT
      LAYER M5 ;
        RECT  55.392 0 55.416 0.192 ;
    END
  END o2[65]
  PIN o2[66]
    DIRECTION OUTPUT ;
    USE SIGNAL ;
    PORT
      LAYER M5 ;
        RECT  55.632 0 55.656 0.192 ;
    END
  END o2[66]
  PIN o2[67]
    DIRECTION OUTPUT ;
    USE SIGNAL ;
    PORT
      LAYER M5 ;
        RECT  55.92 0 55.944 0.192 ;
    END
  END o2[67]
  PIN o2[68]
    DIRECTION OUTPUT ;
    USE SIGNAL ;
    PORT
      LAYER M5 ;
        RECT  56.4 0 56.424 0.192 ;
    END
  END o2[68]
  PIN o2[69]
    DIRECTION OUTPUT ;
    USE SIGNAL ;
    PORT
      LAYER M5 ;
        RECT  56.64 0 56.664 0.192 ;
    END
  END o2[69]
  PIN o2[6]
    DIRECTION OUTPUT ;
    USE SIGNAL ;
    PORT
      LAYER M5 ;
        RECT  40.56 0 40.584 0.192 ;
    END
  END o2[6]
  PIN o2[70]
    DIRECTION OUTPUT ;
    USE SIGNAL ;
    PORT
      LAYER M5 ;
        RECT  56.88 0 56.904 0.192 ;
    END
  END o2[70]
  PIN o2[71]
    DIRECTION OUTPUT ;
    USE SIGNAL ;
    PORT
      LAYER M5 ;
        RECT  57.168 0 57.192 0.192 ;
    END
  END o2[71]
  PIN o2[72]
    DIRECTION OUTPUT ;
    USE SIGNAL ;
    PORT
      LAYER M5 ;
        RECT  57.408 0 57.432 0.192 ;
    END
  END o2[72]
  PIN o2[73]
    DIRECTION OUTPUT ;
    USE SIGNAL ;
    PORT
      LAYER M5 ;
        RECT  57.648 0 57.672 0.192 ;
    END
  END o2[73]
  PIN o2[74]
    DIRECTION OUTPUT ;
    USE SIGNAL ;
    PORT
      LAYER M5 ;
        RECT  57.888 0 57.912 0.192 ;
    END
  END o2[74]
  PIN o2[75]
    DIRECTION OUTPUT ;
    USE SIGNAL ;
    PORT
      LAYER M5 ;
        RECT  58.176 0 58.2 0.192 ;
    END
  END o2[75]
  PIN o2[76]
    DIRECTION OUTPUT ;
    USE SIGNAL ;
    PORT
      LAYER M5 ;
        RECT  58.416 0 58.44 0.192 ;
    END
  END o2[76]
  PIN o2[77]
    DIRECTION OUTPUT ;
    USE SIGNAL ;
    PORT
      LAYER M5 ;
        RECT  58.656 0 58.68 0.192 ;
    END
  END o2[77]
  PIN o2[78]
    DIRECTION OUTPUT ;
    USE SIGNAL ;
    PORT
      LAYER M5 ;
        RECT  58.896 0 58.92 0.192 ;
    END
  END o2[78]
  PIN o2[79]
    DIRECTION OUTPUT ;
    USE SIGNAL ;
    PORT
      LAYER M5 ;
        RECT  59.184 0 59.208 0.192 ;
    END
  END o2[79]
  PIN o2[7]
    DIRECTION OUTPUT ;
    USE SIGNAL ;
    PORT
      LAYER M5 ;
        RECT  40.848 0 40.872 0.192 ;
    END
  END o2[7]
  PIN o2[80]
    DIRECTION OUTPUT ;
    USE SIGNAL ;
    PORT
      LAYER M5 ;
        RECT  59.424 0 59.448 0.192 ;
    END
  END o2[80]
  PIN o2[81]
    DIRECTION OUTPUT ;
    USE SIGNAL ;
    PORT
      LAYER M5 ;
        RECT  59.664 0 59.688 0.192 ;
    END
  END o2[81]
  PIN o2[82]
    DIRECTION OUTPUT ;
    USE SIGNAL ;
    PORT
      LAYER M5 ;
        RECT  59.904 0 59.928 0.192 ;
    END
  END o2[82]
  PIN o2[83]
    DIRECTION OUTPUT ;
    USE SIGNAL ;
    PORT
      LAYER M5 ;
        RECT  60.144 0 60.168 0.192 ;
    END
  END o2[83]
  PIN o2[84]
    DIRECTION OUTPUT ;
    USE SIGNAL ;
    PORT
      LAYER M5 ;
        RECT  60.432 0 60.456 0.192 ;
    END
  END o2[84]
  PIN o2[85]
    DIRECTION OUTPUT ;
    USE SIGNAL ;
    PORT
      LAYER M5 ;
        RECT  60.672 0 60.696 0.192 ;
    END
  END o2[85]
  PIN o2[86]
    DIRECTION OUTPUT ;
    USE SIGNAL ;
    PORT
      LAYER M5 ;
        RECT  60.912 0 60.936 0.192 ;
    END
  END o2[86]
  PIN o2[87]
    DIRECTION OUTPUT ;
    USE SIGNAL ;
    PORT
      LAYER M5 ;
        RECT  61.152 0 61.176 0.192 ;
    END
  END o2[87]
  PIN o2[88]
    DIRECTION OUTPUT ;
    USE SIGNAL ;
    PORT
      LAYER M5 ;
        RECT  61.44 0 61.464 0.192 ;
    END
  END o2[88]
  PIN o2[89]
    DIRECTION OUTPUT ;
    USE SIGNAL ;
    PORT
      LAYER M5 ;
        RECT  61.68 0 61.704 0.192 ;
    END
  END o2[89]
  PIN o2[8]
    DIRECTION OUTPUT ;
    USE SIGNAL ;
    PORT
      LAYER M5 ;
        RECT  41.088 0 41.112 0.192 ;
    END
  END o2[8]
  PIN o2[90]
    DIRECTION OUTPUT ;
    USE SIGNAL ;
    PORT
      LAYER M5 ;
        RECT  61.92 0 61.944 0.192 ;
    END
  END o2[90]
  PIN o2[91]
    DIRECTION OUTPUT ;
    USE SIGNAL ;
    PORT
      LAYER M5 ;
        RECT  62.16 0 62.184 0.192 ;
    END
  END o2[91]
  PIN o2[92]
    DIRECTION OUTPUT ;
    USE SIGNAL ;
    PORT
      LAYER M5 ;
        RECT  62.448 0 62.472 0.192 ;
    END
  END o2[92]
  PIN o2[93]
    DIRECTION OUTPUT ;
    USE SIGNAL ;
    PORT
      LAYER M5 ;
        RECT  62.688 0 62.712 0.192 ;
    END
  END o2[93]
  PIN o2[94]
    DIRECTION OUTPUT ;
    USE SIGNAL ;
    PORT
      LAYER M5 ;
        RECT  62.928 0 62.952 0.192 ;
    END
  END o2[94]
  PIN o2[95]
    DIRECTION OUTPUT ;
    USE SIGNAL ;
    PORT
      LAYER M5 ;
        RECT  63.168 0 63.192 0.192 ;
    END
  END o2[95]
  PIN o2[96]
    DIRECTION OUTPUT ;
    USE SIGNAL ;
    PORT
      LAYER M5 ;
        RECT  63.456 0 63.48 0.192 ;
    END
  END o2[96]
  PIN o2[97]
    DIRECTION OUTPUT ;
    USE SIGNAL ;
    PORT
      LAYER M5 ;
        RECT  63.696 0 63.72 0.192 ;
    END
  END o2[97]
  PIN o2[98]
    DIRECTION OUTPUT ;
    USE SIGNAL ;
    PORT
      LAYER M5 ;
        RECT  63.936 0 63.96 0.192 ;
    END
  END o2[98]
  PIN o2[99]
    DIRECTION OUTPUT ;
    USE SIGNAL ;
    PORT
      LAYER M5 ;
        RECT  64.176 0 64.2 0.192 ;
    END
  END o2[99]
  PIN o2[9]
    DIRECTION OUTPUT ;
    USE SIGNAL ;
    PORT
      LAYER M5 ;
        RECT  41.328 0 41.352 0.192 ;
    END
  END o2[9]
  PIN o3[0]
    DIRECTION OUTPUT ;
    USE SIGNAL ;
    PORT
      LAYER M5 ;
        RECT  50.592 21.408 50.616 21.6 ;
    END
  END o3[0]
  PIN o3[100]
    DIRECTION OUTPUT ;
    USE SIGNAL ;
    PORT
      LAYER M5 ;
        RECT  67.392 21.408 67.416 21.6 ;
    END
  END o3[100]
  PIN o3[101]
    DIRECTION OUTPUT ;
    USE SIGNAL ;
    PORT
      LAYER M5 ;
        RECT  67.584 21.408 67.608 21.6 ;
    END
  END o3[101]
  PIN o3[102]
    DIRECTION OUTPUT ;
    USE SIGNAL ;
    PORT
      LAYER M5 ;
        RECT  67.728 21.408 67.752 21.6 ;
    END
  END o3[102]
  PIN o3[103]
    DIRECTION OUTPUT ;
    USE SIGNAL ;
    PORT
      LAYER M5 ;
        RECT  67.92 21.408 67.944 21.6 ;
    END
  END o3[103]
  PIN o3[104]
    DIRECTION OUTPUT ;
    USE SIGNAL ;
    PORT
      LAYER M5 ;
        RECT  68.064 21.408 68.088 21.6 ;
    END
  END o3[104]
  PIN o3[105]
    DIRECTION OUTPUT ;
    USE SIGNAL ;
    PORT
      LAYER M5 ;
        RECT  68.256 21.408 68.28 21.6 ;
    END
  END o3[105]
  PIN o3[106]
    DIRECTION OUTPUT ;
    USE SIGNAL ;
    PORT
      LAYER M5 ;
        RECT  68.4 21.408 68.424 21.6 ;
    END
  END o3[106]
  PIN o3[107]
    DIRECTION OUTPUT ;
    USE SIGNAL ;
    PORT
      LAYER M5 ;
        RECT  68.544 21.408 68.568 21.6 ;
    END
  END o3[107]
  PIN o3[108]
    DIRECTION OUTPUT ;
    USE SIGNAL ;
    PORT
      LAYER M5 ;
        RECT  68.736 21.408 68.76 21.6 ;
    END
  END o3[108]
  PIN o3[109]
    DIRECTION OUTPUT ;
    USE SIGNAL ;
    PORT
      LAYER M5 ;
        RECT  68.88 21.408 68.904 21.6 ;
    END
  END o3[109]
  PIN o3[10]
    DIRECTION OUTPUT ;
    USE SIGNAL ;
    PORT
      LAYER M5 ;
        RECT  52.272 21.408 52.296 21.6 ;
    END
  END o3[10]
  PIN o3[110]
    DIRECTION OUTPUT ;
    USE SIGNAL ;
    PORT
      LAYER M5 ;
        RECT  69.072 21.408 69.096 21.6 ;
    END
  END o3[110]
  PIN o3[111]
    DIRECTION OUTPUT ;
    USE SIGNAL ;
    PORT
      LAYER M5 ;
        RECT  69.216 21.408 69.24 21.6 ;
    END
  END o3[111]
  PIN o3[112]
    DIRECTION OUTPUT ;
    USE SIGNAL ;
    PORT
      LAYER M5 ;
        RECT  69.408 21.408 69.432 21.6 ;
    END
  END o3[112]
  PIN o3[113]
    DIRECTION OUTPUT ;
    USE SIGNAL ;
    PORT
      LAYER M5 ;
        RECT  69.552 21.408 69.576 21.6 ;
    END
  END o3[113]
  PIN o3[114]
    DIRECTION OUTPUT ;
    USE SIGNAL ;
    PORT
      LAYER M5 ;
        RECT  69.744 21.408 69.768 21.6 ;
    END
  END o3[114]
  PIN o3[115]
    DIRECTION OUTPUT ;
    USE SIGNAL ;
    PORT
      LAYER M5 ;
        RECT  69.888 21.408 69.912 21.6 ;
    END
  END o3[115]
  PIN o3[116]
    DIRECTION OUTPUT ;
    USE SIGNAL ;
    PORT
      LAYER M5 ;
        RECT  70.08 21.408 70.104 21.6 ;
    END
  END o3[116]
  PIN o3[117]
    DIRECTION OUTPUT ;
    USE SIGNAL ;
    PORT
      LAYER M5 ;
        RECT  70.224 21.408 70.248 21.6 ;
    END
  END o3[117]
  PIN o3[118]
    DIRECTION OUTPUT ;
    USE SIGNAL ;
    PORT
      LAYER M5 ;
        RECT  70.416 21.408 70.44 21.6 ;
    END
  END o3[118]
  PIN o3[119]
    DIRECTION OUTPUT ;
    USE SIGNAL ;
    PORT
      LAYER M5 ;
        RECT  70.56 21.408 70.584 21.6 ;
    END
  END o3[119]
  PIN o3[11]
    DIRECTION OUTPUT ;
    USE SIGNAL ;
    PORT
      LAYER M5 ;
        RECT  52.416 21.408 52.44 21.6 ;
    END
  END o3[11]
  PIN o3[120]
    DIRECTION OUTPUT ;
    USE SIGNAL ;
    PORT
      LAYER M5 ;
        RECT  70.752 21.408 70.776 21.6 ;
    END
  END o3[120]
  PIN o3[121]
    DIRECTION OUTPUT ;
    USE SIGNAL ;
    PORT
      LAYER M5 ;
        RECT  70.896 21.408 70.92 21.6 ;
    END
  END o3[121]
  PIN o3[122]
    DIRECTION OUTPUT ;
    USE SIGNAL ;
    PORT
      LAYER M5 ;
        RECT  71.04 21.408 71.064 21.6 ;
    END
  END o3[122]
  PIN o3[123]
    DIRECTION OUTPUT ;
    USE SIGNAL ;
    PORT
      LAYER M5 ;
        RECT  71.232 21.408 71.256 21.6 ;
    END
  END o3[123]
  PIN o3[124]
    DIRECTION OUTPUT ;
    USE SIGNAL ;
    PORT
      LAYER M5 ;
        RECT  71.376 21.408 71.4 21.6 ;
    END
  END o3[124]
  PIN o3[125]
    DIRECTION OUTPUT ;
    USE SIGNAL ;
    PORT
      LAYER M5 ;
        RECT  71.568 21.408 71.592 21.6 ;
    END
  END o3[125]
  PIN o3[126]
    DIRECTION OUTPUT ;
    USE SIGNAL ;
    PORT
      LAYER M5 ;
        RECT  71.712 21.408 71.736 21.6 ;
    END
  END o3[126]
  PIN o3[127]
    DIRECTION OUTPUT ;
    USE SIGNAL ;
    PORT
      LAYER M5 ;
        RECT  71.904 21.408 71.928 21.6 ;
    END
  END o3[127]
  PIN o3[128]
    DIRECTION OUTPUT ;
    USE SIGNAL ;
    PORT
      LAYER M5 ;
        RECT  72.048 21.408 72.072 21.6 ;
    END
  END o3[128]
  PIN o3[129]
    DIRECTION OUTPUT ;
    USE SIGNAL ;
    PORT
      LAYER M5 ;
        RECT  72.24 21.408 72.264 21.6 ;
    END
  END o3[129]
  PIN o3[12]
    DIRECTION OUTPUT ;
    USE SIGNAL ;
    PORT
      LAYER M5 ;
        RECT  52.608 21.408 52.632 21.6 ;
    END
  END o3[12]
  PIN o3[130]
    DIRECTION OUTPUT ;
    USE SIGNAL ;
    PORT
      LAYER M5 ;
        RECT  72.384 21.408 72.408 21.6 ;
    END
  END o3[130]
  PIN o3[131]
    DIRECTION OUTPUT ;
    USE SIGNAL ;
    PORT
      LAYER M5 ;
        RECT  72.576 21.408 72.6 21.6 ;
    END
  END o3[131]
  PIN o3[132]
    DIRECTION OUTPUT ;
    USE SIGNAL ;
    PORT
      LAYER M5 ;
        RECT  72.72 21.408 72.744 21.6 ;
    END
  END o3[132]
  PIN o3[133]
    DIRECTION OUTPUT ;
    USE SIGNAL ;
    PORT
      LAYER M5 ;
        RECT  72.912 21.408 72.936 21.6 ;
    END
  END o3[133]
  PIN o3[134]
    DIRECTION OUTPUT ;
    USE SIGNAL ;
    PORT
      LAYER M5 ;
        RECT  73.056 21.408 73.08 21.6 ;
    END
  END o3[134]
  PIN o3[135]
    DIRECTION OUTPUT ;
    USE SIGNAL ;
    PORT
      LAYER M5 ;
        RECT  73.248 21.408 73.272 21.6 ;
    END
  END o3[135]
  PIN o3[13]
    DIRECTION OUTPUT ;
    USE SIGNAL ;
    PORT
      LAYER M5 ;
        RECT  52.752 21.408 52.776 21.6 ;
    END
  END o3[13]
  PIN o3[14]
    DIRECTION OUTPUT ;
    USE SIGNAL ;
    PORT
      LAYER M5 ;
        RECT  52.896 21.408 52.92 21.6 ;
    END
  END o3[14]
  PIN o3[15]
    DIRECTION OUTPUT ;
    USE SIGNAL ;
    PORT
      LAYER M5 ;
        RECT  53.088 21.408 53.112 21.6 ;
    END
  END o3[15]
  PIN o3[16]
    DIRECTION OUTPUT ;
    USE SIGNAL ;
    PORT
      LAYER M5 ;
        RECT  53.232 21.408 53.256 21.6 ;
    END
  END o3[16]
  PIN o3[17]
    DIRECTION OUTPUT ;
    USE SIGNAL ;
    PORT
      LAYER M5 ;
        RECT  53.424 21.408 53.448 21.6 ;
    END
  END o3[17]
  PIN o3[18]
    DIRECTION OUTPUT ;
    USE SIGNAL ;
    PORT
      LAYER M5 ;
        RECT  53.568 21.408 53.592 21.6 ;
    END
  END o3[18]
  PIN o3[19]
    DIRECTION OUTPUT ;
    USE SIGNAL ;
    PORT
      LAYER M5 ;
        RECT  53.76 21.408 53.784 21.6 ;
    END
  END o3[19]
  PIN o3[1]
    DIRECTION OUTPUT ;
    USE SIGNAL ;
    PORT
      LAYER M5 ;
        RECT  50.736 21.408 50.76 21.6 ;
    END
  END o3[1]
  PIN o3[20]
    DIRECTION OUTPUT ;
    USE SIGNAL ;
    PORT
      LAYER M5 ;
        RECT  53.904 21.408 53.928 21.6 ;
    END
  END o3[20]
  PIN o3[21]
    DIRECTION OUTPUT ;
    USE SIGNAL ;
    PORT
      LAYER M5 ;
        RECT  54.096 21.408 54.12 21.6 ;
    END
  END o3[21]
  PIN o3[22]
    DIRECTION OUTPUT ;
    USE SIGNAL ;
    PORT
      LAYER M5 ;
        RECT  54.24 21.408 54.264 21.6 ;
    END
  END o3[22]
  PIN o3[23]
    DIRECTION OUTPUT ;
    USE SIGNAL ;
    PORT
      LAYER M5 ;
        RECT  54.432 21.408 54.456 21.6 ;
    END
  END o3[23]
  PIN o3[24]
    DIRECTION OUTPUT ;
    USE SIGNAL ;
    PORT
      LAYER M5 ;
        RECT  54.576 21.408 54.6 21.6 ;
    END
  END o3[24]
  PIN o3[25]
    DIRECTION OUTPUT ;
    USE SIGNAL ;
    PORT
      LAYER M5 ;
        RECT  54.768 21.408 54.792 21.6 ;
    END
  END o3[25]
  PIN o3[26]
    DIRECTION OUTPUT ;
    USE SIGNAL ;
    PORT
      LAYER M5 ;
        RECT  54.912 21.408 54.936 21.6 ;
    END
  END o3[26]
  PIN o3[27]
    DIRECTION OUTPUT ;
    USE SIGNAL ;
    PORT
      LAYER M5 ;
        RECT  55.104 21.408 55.128 21.6 ;
    END
  END o3[27]
  PIN o3[28]
    DIRECTION OUTPUT ;
    USE SIGNAL ;
    PORT
      LAYER M5 ;
        RECT  55.248 21.408 55.272 21.6 ;
    END
  END o3[28]
  PIN o3[29]
    DIRECTION OUTPUT ;
    USE SIGNAL ;
    PORT
      LAYER M5 ;
        RECT  55.392 21.408 55.416 21.6 ;
    END
  END o3[29]
  PIN o3[2]
    DIRECTION OUTPUT ;
    USE SIGNAL ;
    PORT
      LAYER M5 ;
        RECT  50.928 21.408 50.952 21.6 ;
    END
  END o3[2]
  PIN o3[30]
    DIRECTION OUTPUT ;
    USE SIGNAL ;
    PORT
      LAYER M5 ;
        RECT  55.584 21.408 55.608 21.6 ;
    END
  END o3[30]
  PIN o3[31]
    DIRECTION OUTPUT ;
    USE SIGNAL ;
    PORT
      LAYER M5 ;
        RECT  55.728 21.408 55.752 21.6 ;
    END
  END o3[31]
  PIN o3[32]
    DIRECTION OUTPUT ;
    USE SIGNAL ;
    PORT
      LAYER M5 ;
        RECT  55.92 21.408 55.944 21.6 ;
    END
  END o3[32]
  PIN o3[33]
    DIRECTION OUTPUT ;
    USE SIGNAL ;
    PORT
      LAYER M5 ;
        RECT  56.064 21.408 56.088 21.6 ;
    END
  END o3[33]
  PIN o3[34]
    DIRECTION OUTPUT ;
    USE SIGNAL ;
    PORT
      LAYER M5 ;
        RECT  56.256 21.408 56.28 21.6 ;
    END
  END o3[34]
  PIN o3[35]
    DIRECTION OUTPUT ;
    USE SIGNAL ;
    PORT
      LAYER M5 ;
        RECT  56.4 21.408 56.424 21.6 ;
    END
  END o3[35]
  PIN o3[36]
    DIRECTION OUTPUT ;
    USE SIGNAL ;
    PORT
      LAYER M5 ;
        RECT  56.592 21.408 56.616 21.6 ;
    END
  END o3[36]
  PIN o3[37]
    DIRECTION OUTPUT ;
    USE SIGNAL ;
    PORT
      LAYER M5 ;
        RECT  56.736 21.408 56.76 21.6 ;
    END
  END o3[37]
  PIN o3[38]
    DIRECTION OUTPUT ;
    USE SIGNAL ;
    PORT
      LAYER M5 ;
        RECT  56.928 21.408 56.952 21.6 ;
    END
  END o3[38]
  PIN o3[39]
    DIRECTION OUTPUT ;
    USE SIGNAL ;
    PORT
      LAYER M5 ;
        RECT  57.072 21.408 57.096 21.6 ;
    END
  END o3[39]
  PIN o3[3]
    DIRECTION OUTPUT ;
    USE SIGNAL ;
    PORT
      LAYER M5 ;
        RECT  51.072 21.408 51.096 21.6 ;
    END
  END o3[3]
  PIN o3[40]
    DIRECTION OUTPUT ;
    USE SIGNAL ;
    PORT
      LAYER M5 ;
        RECT  57.264 21.408 57.288 21.6 ;
    END
  END o3[40]
  PIN o3[41]
    DIRECTION OUTPUT ;
    USE SIGNAL ;
    PORT
      LAYER M5 ;
        RECT  57.408 21.408 57.432 21.6 ;
    END
  END o3[41]
  PIN o3[42]
    DIRECTION OUTPUT ;
    USE SIGNAL ;
    PORT
      LAYER M5 ;
        RECT  57.6 21.408 57.624 21.6 ;
    END
  END o3[42]
  PIN o3[43]
    DIRECTION OUTPUT ;
    USE SIGNAL ;
    PORT
      LAYER M5 ;
        RECT  57.744 21.408 57.768 21.6 ;
    END
  END o3[43]
  PIN o3[44]
    DIRECTION OUTPUT ;
    USE SIGNAL ;
    PORT
      LAYER M5 ;
        RECT  57.936 21.408 57.96 21.6 ;
    END
  END o3[44]
  PIN o3[45]
    DIRECTION OUTPUT ;
    USE SIGNAL ;
    PORT
      LAYER M5 ;
        RECT  58.08 21.408 58.104 21.6 ;
    END
  END o3[45]
  PIN o3[46]
    DIRECTION OUTPUT ;
    USE SIGNAL ;
    PORT
      LAYER M5 ;
        RECT  58.224 21.408 58.248 21.6 ;
    END
  END o3[46]
  PIN o3[47]
    DIRECTION OUTPUT ;
    USE SIGNAL ;
    PORT
      LAYER M5 ;
        RECT  58.416 21.408 58.44 21.6 ;
    END
  END o3[47]
  PIN o3[48]
    DIRECTION OUTPUT ;
    USE SIGNAL ;
    PORT
      LAYER M5 ;
        RECT  58.56 21.408 58.584 21.6 ;
    END
  END o3[48]
  PIN o3[49]
    DIRECTION OUTPUT ;
    USE SIGNAL ;
    PORT
      LAYER M5 ;
        RECT  58.752 21.408 58.776 21.6 ;
    END
  END o3[49]
  PIN o3[4]
    DIRECTION OUTPUT ;
    USE SIGNAL ;
    PORT
      LAYER M5 ;
        RECT  51.264 21.408 51.288 21.6 ;
    END
  END o3[4]
  PIN o3[50]
    DIRECTION OUTPUT ;
    USE SIGNAL ;
    PORT
      LAYER M5 ;
        RECT  58.896 21.408 58.92 21.6 ;
    END
  END o3[50]
  PIN o3[51]
    DIRECTION OUTPUT ;
    USE SIGNAL ;
    PORT
      LAYER M5 ;
        RECT  59.088 21.408 59.112 21.6 ;
    END
  END o3[51]
  PIN o3[52]
    DIRECTION OUTPUT ;
    USE SIGNAL ;
    PORT
      LAYER M5 ;
        RECT  59.232 21.408 59.256 21.6 ;
    END
  END o3[52]
  PIN o3[53]
    DIRECTION OUTPUT ;
    USE SIGNAL ;
    PORT
      LAYER M5 ;
        RECT  59.424 21.408 59.448 21.6 ;
    END
  END o3[53]
  PIN o3[54]
    DIRECTION OUTPUT ;
    USE SIGNAL ;
    PORT
      LAYER M5 ;
        RECT  59.568 21.408 59.592 21.6 ;
    END
  END o3[54]
  PIN o3[55]
    DIRECTION OUTPUT ;
    USE SIGNAL ;
    PORT
      LAYER M5 ;
        RECT  59.76 21.408 59.784 21.6 ;
    END
  END o3[55]
  PIN o3[56]
    DIRECTION OUTPUT ;
    USE SIGNAL ;
    PORT
      LAYER M5 ;
        RECT  59.904 21.408 59.928 21.6 ;
    END
  END o3[56]
  PIN o3[57]
    DIRECTION OUTPUT ;
    USE SIGNAL ;
    PORT
      LAYER M5 ;
        RECT  60.096 21.408 60.12 21.6 ;
    END
  END o3[57]
  PIN o3[58]
    DIRECTION OUTPUT ;
    USE SIGNAL ;
    PORT
      LAYER M5 ;
        RECT  60.24 21.408 60.264 21.6 ;
    END
  END o3[58]
  PIN o3[59]
    DIRECTION OUTPUT ;
    USE SIGNAL ;
    PORT
      LAYER M5 ;
        RECT  60.432 21.408 60.456 21.6 ;
    END
  END o3[59]
  PIN o3[5]
    DIRECTION OUTPUT ;
    USE SIGNAL ;
    PORT
      LAYER M5 ;
        RECT  51.408 21.408 51.432 21.6 ;
    END
  END o3[5]
  PIN o3[60]
    DIRECTION OUTPUT ;
    USE SIGNAL ;
    PORT
      LAYER M5 ;
        RECT  60.576 21.408 60.6 21.6 ;
    END
  END o3[60]
  PIN o3[61]
    DIRECTION OUTPUT ;
    USE SIGNAL ;
    PORT
      LAYER M5 ;
        RECT  60.72 21.408 60.744 21.6 ;
    END
  END o3[61]
  PIN o3[62]
    DIRECTION OUTPUT ;
    USE SIGNAL ;
    PORT
      LAYER M5 ;
        RECT  60.912 21.408 60.936 21.6 ;
    END
  END o3[62]
  PIN o3[63]
    DIRECTION OUTPUT ;
    USE SIGNAL ;
    PORT
      LAYER M5 ;
        RECT  61.056 21.408 61.08 21.6 ;
    END
  END o3[63]
  PIN o3[64]
    DIRECTION OUTPUT ;
    USE SIGNAL ;
    PORT
      LAYER M5 ;
        RECT  61.248 21.408 61.272 21.6 ;
    END
  END o3[64]
  PIN o3[65]
    DIRECTION OUTPUT ;
    USE SIGNAL ;
    PORT
      LAYER M5 ;
        RECT  61.392 21.408 61.416 21.6 ;
    END
  END o3[65]
  PIN o3[66]
    DIRECTION OUTPUT ;
    USE SIGNAL ;
    PORT
      LAYER M5 ;
        RECT  61.584 21.408 61.608 21.6 ;
    END
  END o3[66]
  PIN o3[67]
    DIRECTION OUTPUT ;
    USE SIGNAL ;
    PORT
      LAYER M5 ;
        RECT  61.728 21.408 61.752 21.6 ;
    END
  END o3[67]
  PIN o3[68]
    DIRECTION OUTPUT ;
    USE SIGNAL ;
    PORT
      LAYER M5 ;
        RECT  62.064 21.408 62.088 21.6 ;
    END
  END o3[68]
  PIN o3[69]
    DIRECTION OUTPUT ;
    USE SIGNAL ;
    PORT
      LAYER M5 ;
        RECT  62.256 21.408 62.28 21.6 ;
    END
  END o3[69]
  PIN o3[6]
    DIRECTION OUTPUT ;
    USE SIGNAL ;
    PORT
      LAYER M5 ;
        RECT  51.6 21.408 51.624 21.6 ;
    END
  END o3[6]
  PIN o3[70]
    DIRECTION OUTPUT ;
    USE SIGNAL ;
    PORT
      LAYER M5 ;
        RECT  62.4 21.408 62.424 21.6 ;
    END
  END o3[70]
  PIN o3[71]
    DIRECTION OUTPUT ;
    USE SIGNAL ;
    PORT
      LAYER M5 ;
        RECT  62.592 21.408 62.616 21.6 ;
    END
  END o3[71]
  PIN o3[72]
    DIRECTION OUTPUT ;
    USE SIGNAL ;
    PORT
      LAYER M5 ;
        RECT  62.736 21.408 62.76 21.6 ;
    END
  END o3[72]
  PIN o3[73]
    DIRECTION OUTPUT ;
    USE SIGNAL ;
    PORT
      LAYER M5 ;
        RECT  62.928 21.408 62.952 21.6 ;
    END
  END o3[73]
  PIN o3[74]
    DIRECTION OUTPUT ;
    USE SIGNAL ;
    PORT
      LAYER M5 ;
        RECT  63.072 21.408 63.096 21.6 ;
    END
  END o3[74]
  PIN o3[75]
    DIRECTION OUTPUT ;
    USE SIGNAL ;
    PORT
      LAYER M5 ;
        RECT  63.216 21.408 63.24 21.6 ;
    END
  END o3[75]
  PIN o3[76]
    DIRECTION OUTPUT ;
    USE SIGNAL ;
    PORT
      LAYER M5 ;
        RECT  63.408 21.408 63.432 21.6 ;
    END
  END o3[76]
  PIN o3[77]
    DIRECTION OUTPUT ;
    USE SIGNAL ;
    PORT
      LAYER M5 ;
        RECT  63.552 21.408 63.576 21.6 ;
    END
  END o3[77]
  PIN o3[78]
    DIRECTION OUTPUT ;
    USE SIGNAL ;
    PORT
      LAYER M5 ;
        RECT  63.744 21.408 63.768 21.6 ;
    END
  END o3[78]
  PIN o3[79]
    DIRECTION OUTPUT ;
    USE SIGNAL ;
    PORT
      LAYER M5 ;
        RECT  63.888 21.408 63.912 21.6 ;
    END
  END o3[79]
  PIN o3[7]
    DIRECTION OUTPUT ;
    USE SIGNAL ;
    PORT
      LAYER M5 ;
        RECT  51.744 21.408 51.768 21.6 ;
    END
  END o3[7]
  PIN o3[80]
    DIRECTION OUTPUT ;
    USE SIGNAL ;
    PORT
      LAYER M5 ;
        RECT  64.08 21.408 64.104 21.6 ;
    END
  END o3[80]
  PIN o3[81]
    DIRECTION OUTPUT ;
    USE SIGNAL ;
    PORT
      LAYER M5 ;
        RECT  64.224 21.408 64.248 21.6 ;
    END
  END o3[81]
  PIN o3[82]
    DIRECTION OUTPUT ;
    USE SIGNAL ;
    PORT
      LAYER M5 ;
        RECT  64.416 21.408 64.44 21.6 ;
    END
  END o3[82]
  PIN o3[83]
    DIRECTION OUTPUT ;
    USE SIGNAL ;
    PORT
      LAYER M5 ;
        RECT  64.56 21.408 64.584 21.6 ;
    END
  END o3[83]
  PIN o3[84]
    DIRECTION OUTPUT ;
    USE SIGNAL ;
    PORT
      LAYER M5 ;
        RECT  64.752 21.408 64.776 21.6 ;
    END
  END o3[84]
  PIN o3[85]
    DIRECTION OUTPUT ;
    USE SIGNAL ;
    PORT
      LAYER M5 ;
        RECT  64.896 21.408 64.92 21.6 ;
    END
  END o3[85]
  PIN o3[86]
    DIRECTION OUTPUT ;
    USE SIGNAL ;
    PORT
      LAYER M5 ;
        RECT  65.088 21.408 65.112 21.6 ;
    END
  END o3[86]
  PIN o3[87]
    DIRECTION OUTPUT ;
    USE SIGNAL ;
    PORT
      LAYER M5 ;
        RECT  65.232 21.408 65.256 21.6 ;
    END
  END o3[87]
  PIN o3[88]
    DIRECTION OUTPUT ;
    USE SIGNAL ;
    PORT
      LAYER M5 ;
        RECT  65.424 21.408 65.448 21.6 ;
    END
  END o3[88]
  PIN o3[89]
    DIRECTION OUTPUT ;
    USE SIGNAL ;
    PORT
      LAYER M5 ;
        RECT  65.568 21.408 65.592 21.6 ;
    END
  END o3[89]
  PIN o3[8]
    DIRECTION OUTPUT ;
    USE SIGNAL ;
    PORT
      LAYER M5 ;
        RECT  51.936 21.408 51.96 21.6 ;
    END
  END o3[8]
  PIN o3[90]
    DIRECTION OUTPUT ;
    USE SIGNAL ;
    PORT
      LAYER M5 ;
        RECT  65.76 21.408 65.784 21.6 ;
    END
  END o3[90]
  PIN o3[91]
    DIRECTION OUTPUT ;
    USE SIGNAL ;
    PORT
      LAYER M5 ;
        RECT  65.904 21.408 65.928 21.6 ;
    END
  END o3[91]
  PIN o3[92]
    DIRECTION OUTPUT ;
    USE SIGNAL ;
    PORT
      LAYER M5 ;
        RECT  66.048 21.408 66.072 21.6 ;
    END
  END o3[92]
  PIN o3[93]
    DIRECTION OUTPUT ;
    USE SIGNAL ;
    PORT
      LAYER M5 ;
        RECT  66.24 21.408 66.264 21.6 ;
    END
  END o3[93]
  PIN o3[94]
    DIRECTION OUTPUT ;
    USE SIGNAL ;
    PORT
      LAYER M5 ;
        RECT  66.384 21.408 66.408 21.6 ;
    END
  END o3[94]
  PIN o3[95]
    DIRECTION OUTPUT ;
    USE SIGNAL ;
    PORT
      LAYER M5 ;
        RECT  66.576 21.408 66.6 21.6 ;
    END
  END o3[95]
  PIN o3[96]
    DIRECTION OUTPUT ;
    USE SIGNAL ;
    PORT
      LAYER M5 ;
        RECT  66.72 21.408 66.744 21.6 ;
    END
  END o3[96]
  PIN o3[97]
    DIRECTION OUTPUT ;
    USE SIGNAL ;
    PORT
      LAYER M5 ;
        RECT  66.912 21.408 66.936 21.6 ;
    END
  END o3[97]
  PIN o3[98]
    DIRECTION OUTPUT ;
    USE SIGNAL ;
    PORT
      LAYER M5 ;
        RECT  67.056 21.408 67.08 21.6 ;
    END
  END o3[98]
  PIN o3[99]
    DIRECTION OUTPUT ;
    USE SIGNAL ;
    PORT
      LAYER M5 ;
        RECT  67.248 21.408 67.272 21.6 ;
    END
  END o3[99]
  PIN o3[9]
    DIRECTION OUTPUT ;
    USE SIGNAL ;
    PORT
      LAYER M5 ;
        RECT  52.08 21.408 52.104 21.6 ;
    END
  END o3[9]
  PIN rs
    DIRECTION INPUT ;
    USE SIGNAL ;
    PORT
      LAYER M4 ;
        RECT  0 10.8 0.192 10.824 ;
    END
  END rs
  PIN VDD
    DIRECTION INOUT ;
    USE POWER ;
    PORT
      LAYER M5 ;
        RECT  75.492 2.151 75.612 19.449 ;
        RECT  72.792 2.151 72.912 19.449 ;
        RECT  70.092 2.151 70.212 19.449 ;
        RECT  67.392 2.151 67.512 19.449 ;
        RECT  64.692 2.151 64.812 19.449 ;
        RECT  61.992 2.151 62.112 19.449 ;
        RECT  59.292 2.151 59.412 19.449 ;
        RECT  56.592 2.151 56.712 19.449 ;
        RECT  53.892 2.151 54.012 19.449 ;
        RECT  51.192 2.151 51.312 19.449 ;
        RECT  48.492 2.151 48.612 19.449 ;
        RECT  45.792 2.151 45.912 19.449 ;
        RECT  43.092 2.151 43.212 19.449 ;
        RECT  40.392 2.151 40.512 19.449 ;
        RECT  37.692 2.151 37.812 19.449 ;
        RECT  34.992 2.151 35.112 19.449 ;
        RECT  32.292 2.151 32.412 19.449 ;
        RECT  29.592 2.151 29.712 19.449 ;
        RECT  26.892 2.151 27.012 19.449 ;
        RECT  24.192 2.151 24.312 19.449 ;
        RECT  21.492 2.151 21.612 19.449 ;
        RECT  18.792 2.151 18.912 19.449 ;
        RECT  16.092 2.151 16.212 19.449 ;
        RECT  13.392 2.151 13.512 19.449 ;
        RECT  10.692 2.151 10.812 19.449 ;
        RECT  7.992 2.151 8.112 19.449 ;
        RECT  5.292 2.151 5.412 19.449 ;
        RECT  2.592 2.151 2.712 19.449 ;
    END
  END VDD
  PIN VSS
    DIRECTION INOUT ;
    USE GROUND ;
    PORT
      LAYER M5 ;
        RECT  75.3 2.137 75.42 19.463 ;
        RECT  72.6 2.137 72.72 19.463 ;
        RECT  69.9 2.137 70.02 19.463 ;
        RECT  67.2 2.137 67.32 19.463 ;
        RECT  64.5 2.137 64.62 19.463 ;
        RECT  61.8 2.137 61.92 19.463 ;
        RECT  59.1 2.137 59.22 19.463 ;
        RECT  56.4 2.137 56.52 19.463 ;
        RECT  53.7 2.137 53.82 19.463 ;
        RECT  51 2.137 51.12 19.463 ;
        RECT  48.3 2.137 48.42 19.463 ;
        RECT  45.6 2.137 45.72 19.463 ;
        RECT  42.9 2.137 43.02 19.463 ;
        RECT  40.2 2.137 40.32 19.463 ;
        RECT  37.5 2.137 37.62 19.463 ;
        RECT  34.8 2.137 34.92 19.463 ;
        RECT  32.1 2.137 32.22 19.463 ;
        RECT  29.4 2.137 29.52 19.463 ;
        RECT  26.7 2.137 26.82 19.463 ;
        RECT  24 2.137 24.12 19.463 ;
        RECT  21.3 2.137 21.42 19.463 ;
        RECT  18.6 2.137 18.72 19.463 ;
        RECT  15.9 2.137 16.02 19.463 ;
        RECT  13.2 2.137 13.32 19.463 ;
        RECT  10.5 2.137 10.62 19.463 ;
        RECT  7.8 2.137 7.92 19.463 ;
        RECT  5.1 2.137 5.22 19.463 ;
        RECT  2.4 2.137 2.52 19.463 ;
    END
  END VSS
  OBS
    LAYER RVTN ;
     RECT  2.16 2.16 75.6 2.295 ;
     RECT  2.16 2.565 75.6 2.835 ;
     RECT  2.16 3.105 75.6 3.375 ;
     RECT  2.16 3.645 75.6 3.915 ;
     RECT  2.16 4.185 75.6 4.455 ;
     RECT  2.16 4.725 75.6 4.995 ;
     RECT  2.16 5.265 75.6 5.535 ;
     RECT  2.16 5.805 75.6 6.075 ;
     RECT  2.16 6.345 75.6 6.615 ;
     RECT  2.16 6.885 75.6 7.155 ;
     RECT  2.16 7.425 75.6 7.695 ;
     RECT  2.16 7.965 75.6 8.235 ;
     RECT  2.16 8.505 75.6 8.775 ;
     RECT  2.16 9.045 75.6 9.315 ;
     RECT  2.16 9.585 75.6 9.855 ;
     RECT  2.16 10.125 75.6 10.395 ;
     RECT  2.16 10.665 75.6 10.935 ;
     RECT  2.16 11.205 75.6 11.475 ;
     RECT  2.16 11.745 75.6 12.015 ;
     RECT  2.16 12.285 75.6 12.555 ;
     RECT  2.16 12.825 75.6 13.095 ;
     RECT  2.16 13.365 75.6 13.635 ;
     RECT  2.16 13.905 75.6 14.175 ;
     RECT  2.16 14.445 75.6 14.715 ;
     RECT  2.16 14.985 75.6 15.255 ;
     RECT  2.16 15.525 75.6 15.795 ;
     RECT  2.16 16.065 75.6 16.335 ;
     RECT  2.16 16.605 75.6 16.875 ;
     RECT  2.16 17.145 75.6 17.415 ;
     RECT  2.16 17.685 75.6 17.955 ;
     RECT  2.16 18.225 75.6 18.495 ;
     RECT  2.16 18.765 75.6 19.035 ;
     RECT  2.16 19.305 75.6 19.44 ;
    LAYER RVTP ;
     RECT  2.16 2.295 75.6 2.565 ;
     RECT  2.16 2.835 75.6 3.105 ;
     RECT  2.16 3.375 75.6 3.645 ;
     RECT  2.16 3.915 75.6 4.185 ;
     RECT  2.16 4.455 75.6 4.725 ;
     RECT  2.16 4.995 75.6 5.265 ;
     RECT  2.16 5.535 75.6 5.805 ;
     RECT  2.16 6.075 75.6 6.345 ;
     RECT  2.16 6.615 75.6 6.885 ;
     RECT  2.16 7.155 75.6 7.425 ;
     RECT  2.16 7.695 75.6 7.965 ;
     RECT  2.16 8.235 75.6 8.505 ;
     RECT  2.16 8.775 75.6 9.045 ;
     RECT  2.16 9.315 75.6 9.585 ;
     RECT  2.16 9.855 75.6 10.125 ;
     RECT  2.16 10.395 75.6 10.665 ;
     RECT  2.16 10.935 75.6 11.205 ;
     RECT  2.16 11.475 75.6 11.745 ;
     RECT  2.16 12.015 75.6 12.285 ;
     RECT  2.16 12.555 75.6 12.825 ;
     RECT  2.16 13.095 75.6 13.365 ;
     RECT  2.16 13.635 75.6 13.905 ;
     RECT  2.16 14.175 75.6 14.445 ;
     RECT  2.16 14.715 75.6 14.985 ;
     RECT  2.16 15.255 75.6 15.525 ;
     RECT  2.16 15.795 75.6 16.065 ;
     RECT  2.16 16.335 75.6 16.605 ;
     RECT  2.16 16.875 75.6 17.145 ;
     RECT  2.16 17.415 75.6 17.685 ;
     RECT  2.16 17.955 75.6 18.225 ;
     RECT  2.16 18.495 75.6 18.765 ;
     RECT  2.16 19.035 75.6 19.305 ;
    LAYER M1 ;
     RECT  2.16 2.151 75.6 19.449 ;
    LAYER M2 ;
     RECT  2.16 2.151 23.935 19.449 ;
     RECT  23.935 2.106 24.791 19.449 ;
     RECT  24.791 2.151 35.311 19.449 ;
     RECT  35.311 2.106 35.915 19.449 ;
     RECT  35.915 2.151 75.6 19.449 ;
     RECT  75.6 2.421 75.612 19.179 ;
    LAYER M3 ;
     RECT  42.084 0.187 42.102 0.523 ;
     RECT  65.196 0.187 66.006 0.523 ;
     RECT  68.22 0.187 68.238 0.523 ;
     RECT  40.86 0.187 40.878 0.571 ;
     RECT  43.416 0.187 44.874 0.571 ;
     RECT  45.936 0.187 45.954 0.571 ;
     RECT  49.896 0.187 49.914 0.571 ;
     RECT  69.228 0.187 69.246 0.571 ;
     RECT  41.724 0.523 42.102 1.099 ;
     RECT  43.416 0.571 45.954 1.099 ;
     RECT  46.908 0.187 46.926 1.099 ;
     RECT  49.032 0.571 49.914 1.099 ;
     RECT  50.868 0.571 50.886 1.099 ;
     RECT  57.924 0.187 58.23 1.099 ;
     RECT  60.804 0.571 60.822 1.099 ;
     RECT  61.776 0.571 61.794 1.099 ;
     RECT  63.108 0.523 63.126 1.099 ;
     RECT  63.936 0.523 66.006 1.099 ;
     RECT  67.536 0.523 68.238 1.099 ;
     RECT  69.084 0.571 69.246 1.099 ;
     RECT  70.236 0.187 70.686 1.099 ;
     RECT  16.38 0.187 16.398 1.147 ;
     RECT  52.92 0.187 52.938 1.147 ;
     RECT  53.856 1.099 54.126 1.147 ;
     RECT  63.108 1.099 66.006 1.147 ;
     RECT  67.176 1.099 70.686 1.147 ;
     RECT  51.912 0.187 51.93 1.627 ;
     RECT  52.92 1.147 54.126 1.627 ;
     RECT  51.912 1.627 54.126 1.675 ;
     RECT  54.936 0.187 55.422 1.675 ;
     RECT  57.096 1.099 58.23 1.675 ;
     RECT  59.076 0.523 59.094 1.675 ;
     RECT  59.94 0.571 59.958 1.675 ;
     RECT  71.46 1.099 71.478 1.675 ;
     RECT  7.992 0.571 8.01 1.723 ;
     RECT  16.38 1.147 17.118 1.723 ;
     RECT  23.436 1.675 23.454 1.723 ;
     RECT  28.44 0.187 28.458 1.723 ;
     RECT  35.928 1.147 35.946 1.723 ;
     RECT  38.988 0.187 39.582 1.723 ;
     RECT  40.356 0.571 40.878 1.723 ;
     RECT  41.724 1.099 46.926 1.723 ;
     RECT  47.664 1.147 47.682 1.723 ;
     RECT  49.032 1.099 50.886 1.723 ;
     RECT  51.912 1.675 55.638 1.723 ;
     RECT  57.096 1.675 59.958 1.723 ;
     RECT  60.804 1.099 60.858 1.723 ;
     RECT  61.776 1.099 62.154 1.723 ;
     RECT  63.108 1.147 70.686 1.723 ;
     RECT  71.46 1.675 72.162 1.723 ;
     RECT  73.332 0.571 73.35 1.723 ;
     RECT  4.536 1.723 21.078 1.819 ;
     RECT  21.888 1.723 73.35 1.819 ;
     RECT  4.536 1.819 73.35 2.255 ;
     RECT  2.415 2.143 2.505 2.413 ;
     RECT  75.315 2.143 75.405 2.413 ;
     RECT  4.572 2.255 73.35 3.029 ;
     RECT  4.572 3.029 73.206 3.065 ;
     RECT  4.716 3.065 73.206 3.299 ;
     RECT  4.716 3.299 73.098 3.569 ;
     RECT  4.716 3.569 72.897 3.991 ;
     RECT  4.572 3.991 72.897 4.685 ;
     RECT  5.004 4.685 72.897 4.955 ;
     RECT  5.115 4.955 72.897 5.189 ;
     RECT  5.115 5.189 54.918 5.459 ;
     RECT  44.028 5.459 46.998 5.639 ;
     RECT  47.808 5.459 54.918 5.729 ;
     RECT  50.904 5.729 54.918 5.999 ;
     RECT  47.808 5.729 49.482 6.179 ;
     RECT  2.415 2.413 2.697 8.977 ;
     RECT  2.415 8.977 3.258 9.049 ;
     RECT  2.34 9.049 3.258 9.121 ;
     RECT  2.34 9.121 3.618 9.247 ;
     RECT  2.34 9.247 3.978 9.293 ;
     RECT  2.415 9.293 3.978 9.319 ;
     RECT  5.115 5.459 43.29 9.391 ;
     RECT  2.415 9.319 4.194 9.553 ;
     RECT  4.932 9.391 43.29 9.553 ;
     RECT  2.415 9.553 43.29 9.779 ;
     RECT  3.6 9.779 43.29 9.887 ;
     RECT  3.6 9.887 3.726 10.049 ;
     RECT  3.6 10.049 3.618 10.085 ;
     RECT  4.5 9.887 43.29 10.085 ;
     RECT  2.415 9.779 2.697 10.165 ;
     RECT  4.572 10.085 43.29 10.319 ;
     RECT  4.716 10.319 43.29 10.391 ;
     RECT  2.304 10.165 2.697 10.597 ;
     RECT  2.268 10.597 2.697 10.829 ;
     RECT  5.115 10.391 43.29 12.559 ;
     RECT  44.028 5.639 46.926 12.559 ;
     RECT  5.115 12.559 46.926 12.757 ;
     RECT  47.808 6.179 49.41 12.757 ;
     RECT  5.115 12.757 49.41 13.369 ;
     RECT  5.115 13.369 49.95 13.441 ;
     RECT  50.904 5.999 51.354 13.639 ;
     RECT  5.115 13.441 50.022 13.711 ;
     RECT  50.868 13.639 51.354 13.711 ;
     RECT  5.115 13.711 51.354 13.801 ;
     RECT  56.196 5.189 72.897 13.873 ;
     RECT  5.115 13.801 51.426 13.901 ;
     RECT  52.344 5.999 54.918 14.477 ;
     RECT  5.115 13.901 51.354 14.791 ;
     RECT  52.344 14.477 53.997 14.791 ;
     RECT  54.72 14.477 54.918 15.061 ;
     RECT  55.908 13.873 72.897 15.061 ;
     RECT  5.115 14.791 53.997 15.499 ;
     RECT  54.72 15.061 72.897 15.499 ;
     RECT  5.115 15.499 72.897 17.761 ;
     RECT  5.04 17.761 72.897 18.031 ;
     RECT  5.04 18.031 73.098 18.893 ;
     RECT  5.04 18.893 19.026 18.959 ;
     RECT  5.04 18.959 18.99 19.103 ;
     RECT  5.04 19.103 6.534 19.111 ;
     RECT  2.415 10.829 2.697 19.187 ;
     RECT  75.315 2.413 75.597 19.187 ;
     RECT  19.836 18.893 73.098 19.201 ;
     RECT  4.68 19.111 6.534 19.265 ;
     RECT  7.38 19.103 18.99 19.265 ;
     RECT  5.112 19.265 6.534 19.277 ;
     RECT  7.38 19.265 14.238 19.277 ;
     RECT  17.244 19.265 17.658 19.277 ;
     RECT  5.115 19.277 6.534 19.301 ;
     RECT  19.836 19.201 73.242 19.301 ;
     RECT  5.115 19.301 6.246 19.373 ;
     RECT  6.228 19.373 6.246 19.379 ;
     RECT  7.38 19.277 13.878 19.379 ;
     RECT  17.244 19.277 17.55 19.379 ;
     RECT  19.836 19.301 41.346 19.421 ;
     RECT  2.415 19.187 2.505 19.457 ;
     RECT  5.115 19.373 5.454 19.457 ;
     RECT  75.315 19.187 75.405 19.457 ;
     RECT  5.328 19.457 5.454 19.565 ;
     RECT  42.084 19.301 73.242 19.565 ;
     RECT  7.776 19.379 13.878 19.613 ;
     RECT  15.156 19.265 16.398 19.613 ;
     RECT  19.836 19.421 27.414 19.661 ;
     RECT  5.436 19.565 5.454 19.997 ;
     RECT  7.776 19.613 12.906 19.997 ;
     RECT  13.68 19.613 13.878 19.997 ;
     RECT  15.156 19.613 15.498 19.997 ;
     RECT  17.316 19.379 17.55 19.997 ;
     RECT  19.836 19.661 21.474 19.997 ;
     RECT  22.212 19.661 27.414 19.997 ;
     RECT  28.476 19.421 41.346 19.997 ;
     RECT  42.084 19.565 48.15 19.997 ;
     RECT  49.284 19.565 73.242 19.997 ;
     RECT  22.536 19.997 22.554 20.045 ;
     RECT  29.304 19.997 32.094 20.045 ;
     RECT  34.2 19.997 34.794 20.045 ;
     RECT  36.036 19.997 41.346 20.045 ;
     RECT  49.788 19.997 56.394 20.045 ;
     RECT  58.608 19.997 67.122 20.045 ;
     RECT  67.932 19.997 72.27 20.045 ;
     RECT  30.276 20.045 32.094 20.093 ;
     RECT  49.788 20.045 55.278 20.093 ;
     RECT  72.252 20.045 72.27 20.093 ;
     RECT  49.788 20.093 52.434 20.237 ;
     RECT  7.776 19.997 8.262 20.573 ;
     RECT  9.648 19.997 10.458 20.573 ;
     RECT  11.232 19.997 11.97 20.573 ;
     RECT  12.888 19.997 12.906 20.573 ;
     RECT  15.48 19.997 15.498 20.573 ;
     RECT  16.38 19.613 16.398 20.573 ;
     RECT  17.316 19.997 17.334 20.573 ;
     RECT  18.432 19.265 18.99 20.573 ;
     RECT  20.34 19.997 20.898 20.573 ;
     RECT  24.156 19.997 24.174 20.573 ;
     RECT  25.2 19.997 25.218 20.573 ;
     RECT  26.604 19.997 27.414 20.573 ;
     RECT  29.304 20.045 29.322 20.573 ;
     RECT  30.276 20.093 31.59 20.573 ;
     RECT  33.192 19.997 33.318 20.573 ;
     RECT  34.2 20.045 34.506 20.573 ;
     RECT  36.036 20.045 37.494 20.573 ;
     RECT  38.376 20.045 41.346 20.573 ;
     RECT  42.12 19.997 45.306 20.573 ;
     RECT  46.224 19.997 48.15 20.573 ;
     RECT  50.148 20.237 52.434 20.573 ;
     RECT  53.172 20.093 53.226 20.573 ;
     RECT  54.036 20.093 55.278 20.573 ;
     RECT  56.376 20.045 56.394 20.573 ;
     RECT  57.276 19.997 57.69 20.573 ;
     RECT  58.788 20.045 66.906 20.573 ;
     RECT  67.932 20.045 71.37 20.573 ;
     RECT  73.08 19.997 73.098 20.573 ;
     RECT  30.276 20.573 30.294 20.621 ;
     RECT  33.192 20.573 33.21 20.621 ;
     RECT  36.936 20.573 37.494 20.621 ;
     RECT  43.236 20.573 43.254 20.621 ;
     RECT  47.124 20.573 47.142 20.621 ;
     RECT  50.976 20.573 51.498 20.621 ;
     RECT  54.036 20.573 54.054 20.621 ;
     RECT  55.008 20.573 55.026 20.621 ;
     RECT  57.348 20.573 57.366 20.621 ;
     RECT  59.004 20.573 59.706 20.621 ;
     RECT  61.128 20.573 62.19 20.621 ;
     RECT  64.944 20.573 65.682 20.621 ;
     RECT  67.968 20.573 69.318 20.621 ;
     RECT  70.308 20.573 70.686 20.621 ;
     RECT  20.34 20.573 20.358 20.669 ;
     RECT  50.976 20.621 51.354 20.669 ;
     RECT  59.688 20.621 59.706 20.669 ;
     RECT  66.816 20.573 66.834 20.669 ;
     RECT  67.968 20.621 68.67 20.669 ;
     RECT  50.976 20.669 50.994 20.717 ;
     RECT  61.128 20.621 61.794 20.717 ;
     RECT  70.488 20.621 70.686 20.717 ;
     RECT  61.776 20.717 61.794 20.765 ;
     RECT  68.004 20.669 68.022 20.765 ;
     RECT  53.208 20.573 53.226 21.485 ;
    LAYER M4 ;
     RECT  2.329 9.264 2.408 9.288 ;
     RECT  0.156 10.8 2.408 10.824 ;
     RECT  2.408 2.148 2.512 19.452 ;
     RECT  2.512 2.418 2.704 19.182 ;
     RECT  2.704 9.264 3.233 9.672 ;
     RECT  4.501 19.2 4.645 19.224 ;
     RECT  4.645 18.816 4.981 19.224 ;
     RECT  4.481 1.728 5.108 1.752 ;
     RECT  4.789 4.512 5.108 4.536 ;
     RECT  4.789 5.616 5.108 5.64 ;
     RECT  3.233 9.648 5.108 9.672 ;
     RECT  4.981 18.816 5.108 19.272 ;
     RECT  5.108 1.728 5.173 19.452 ;
     RECT  5.173 1.728 5.404 19.992 ;
     RECT  5.404 18.144 5.465 19.992 ;
     RECT  6.433 3.984 6.505 4.008 ;
     RECT  5.404 1.728 6.541 2.328 ;
     RECT  6.505 3.984 6.541 4.152 ;
     RECT  6.541 1.728 6.659 4.152 ;
     RECT  6.659 1.728 6.697 3.096 ;
     RECT  5.404 5.136 6.973 5.16 ;
     RECT  6.659 4.128 7.333 4.152 ;
     RECT  6.973 5.136 7.333 5.832 ;
     RECT  5.465 18.144 7.669 19.368 ;
     RECT  6.697 1.728 7.808 2.04 ;
     RECT  6.697 3.072 7.808 3.096 ;
     RECT  7.333 4.128 7.808 5.832 ;
     RECT  7.669 18.144 7.808 20.568 ;
     RECT  7.981 0.576 8.065 0.6 ;
     RECT  7.808 1.728 8.104 20.568 ;
     RECT  8.104 18.816 8.243 20.568 ;
     RECT  8.243 19.968 8.273 20.568 ;
     RECT  8.243 18.816 8.531 18.936 ;
     RECT  8.104 3.696 8.597 4.728 ;
     RECT  8.597 3.696 8.819 4.536 ;
     RECT  8.104 5.712 8.957 6.12 ;
     RECT  8.273 19.968 8.993 19.992 ;
     RECT  8.819 3.696 9.421 3.72 ;
     RECT  8.104 14.784 9.493 15.384 ;
     RECT  9.421 3.024 9.781 3.72 ;
     RECT  8.957 5.808 9.961 6.12 ;
     RECT  8.104 1.728 10.177 1.752 ;
     RECT  9.781 3.024 10.177 3.96 ;
     RECT  9.493 14.784 10.249 15.912 ;
     RECT  9.961 5.184 10.321 6.12 ;
     RECT  10.321 5.184 10.357 6.312 ;
     RECT  8.531 18.816 10.393 18.84 ;
     RECT  9.301 20.544 10.393 20.568 ;
     RECT  10.177 1.728 10.508 3.96 ;
     RECT  10.357 5.04 10.508 6.312 ;
     RECT  10.249 14.784 10.508 16.824 ;
     RECT  10.393 18.816 10.508 20.568 ;
     RECT  10.508 1.728 10.793 20.568 ;
     RECT  10.793 1.728 10.804 19.56 ;
     RECT  10.804 18.768 10.924 19.56 ;
     RECT  10.924 18.768 10.945 19.464 ;
     RECT  10.804 2.88 11.053 3.96 ;
     RECT  10.804 5.136 11.053 6.312 ;
     RECT  11.053 5.184 11.117 6.312 ;
     RECT  10.945 18.768 11.729 19.368 ;
     RECT  10.804 16.8 11.977 16.824 ;
     RECT  11.729 19.2 11.989 19.368 ;
     RECT  10.793 20.544 11.989 20.568 ;
     RECT  11.117 5.184 12.373 5.832 ;
     RECT  10.804 14.208 12.481 14.808 ;
     RECT  11.977 16.272 12.517 16.824 ;
     RECT  12.517 16.272 12.733 16.872 ;
     RECT  11.053 2.88 12.913 3.816 ;
     RECT  11.989 19.2 12.917 20.568 ;
     RECT  10.804 1.728 13.013 1.752 ;
     RECT  12.913 2.88 13.093 3.96 ;
     RECT  12.373 5.136 13.093 5.832 ;
     RECT  13.013 1.728 13.208 1.848 ;
     RECT  13.093 2.88 13.208 5.832 ;
     RECT  12.481 13.92 13.208 14.808 ;
     RECT  12.733 16.272 13.208 17.688 ;
     RECT  12.917 19.2 13.208 19.992 ;
     RECT  13.208 1.728 13.504 19.992 ;
     RECT  13.504 2.88 13.619 5.928 ;
     RECT  13.504 13.92 13.745 19.992 ;
     RECT  13.619 2.88 13.852 5.832 ;
     RECT  13.745 16.8 13.9 19.992 ;
     RECT  13.9 16.8 14.249 19.272 ;
     RECT  13.745 13.92 14.821 15.768 ;
     RECT  14.249 16.8 14.821 18.84 ;
     RECT  14.821 13.92 14.905 18.84 ;
     RECT  14.905 16.8 15.289 18.84 ;
     RECT  15.116 19.968 15.289 19.992 ;
     RECT  13.852 2.88 15.361 3.432 ;
     RECT  13.852 4.416 15.361 5.832 ;
     RECT  15.289 16.8 15.452 19.992 ;
     RECT  13.504 1.728 15.721 1.752 ;
     RECT  15.361 2.88 15.721 5.832 ;
     RECT  15.721 1.728 15.908 6.024 ;
     RECT  14.905 13.92 15.908 15.768 ;
     RECT  15.452 16.8 15.908 20.568 ;
     RECT  15.908 1.728 16.204 20.568 ;
     RECT  16.369 0.192 16.595 0.216 ;
     RECT  16.204 1.728 17.077 6.264 ;
     RECT  17.077 1.152 17.164 6.264 ;
     RECT  16.204 13.92 17.345 20.568 ;
     RECT  17.345 13.92 17.561 19.992 ;
     RECT  17.164 1.728 18.608 6.264 ;
     RECT  17.561 13.92 18.608 19.272 ;
     RECT  18.608 1.728 18.661 19.452 ;
     RECT  18.325 20.544 18.661 20.568 ;
     RECT  18.661 1.728 18.904 20.568 ;
     RECT  18.904 13.92 19.397 20.568 ;
     RECT  19.397 14.112 20.293 20.568 ;
     RECT  20.293 14.112 20.38 20.664 ;
     RECT  20.38 14.112 20.509 20.568 ;
     RECT  18.904 1.728 20.78 5.112 ;
     RECT  18.904 6.096 20.78 6.12 ;
     RECT  20.509 14.064 20.909 20.568 ;
     RECT  20.78 1.728 21.308 6.12 ;
     RECT  20.909 14.064 21.308 19.992 ;
     RECT  21.308 1.728 21.604 19.992 ;
     RECT  21.604 13.92 22.453 19.992 ;
     RECT  22.453 13.92 22.565 20.04 ;
     RECT  22.565 13.92 22.811 19.992 ;
     RECT  21.604 1.728 23.4 5.832 ;
     RECT  22.811 13.872 23.533 19.992 ;
     RECT  23.4 1.68 23.651 5.832 ;
     RECT  23.651 1.728 24.008 5.832 ;
     RECT  23.533 13.824 24.008 19.992 ;
     RECT  24.008 1.728 24.133 19.992 ;
     RECT  24.133 1.728 24.304 20.568 ;
     RECT  24.304 13.728 25.229 20.568 ;
     RECT  25.229 13.728 25.301 19.992 ;
     RECT  24.304 1.728 26.197 5.832 ;
     RECT  25.301 13.92 26.293 19.992 ;
     RECT  26.293 13.92 26.521 20.568 ;
     RECT  26.197 1.728 26.708 5.976 ;
     RECT  26.521 13.296 26.708 20.568 ;
     RECT  26.708 1.728 27.004 20.568 ;
     RECT  27.004 13.296 27.731 20.568 ;
     RECT  28.429 0.192 28.643 0.216 ;
     RECT  27.731 13.296 29.293 20.232 ;
     RECT  27.004 1.728 29.408 5.832 ;
     RECT  29.293 13.296 29.408 20.568 ;
     RECT  29.408 1.728 29.704 20.568 ;
     RECT  29.704 13.296 30.265 20.568 ;
     RECT  30.265 13.296 30.755 20.616 ;
     RECT  30.755 13.296 30.841 20.568 ;
     RECT  30.841 13.248 31.612 20.568 ;
     RECT  29.704 1.728 32.108 6.12 ;
     RECT  31.612 13.248 32.108 20.088 ;
     RECT  32.108 1.728 32.404 20.088 ;
     RECT  32.404 13.296 32.501 20.088 ;
     RECT  32.404 1.728 32.537 6.12 ;
     RECT  32.537 1.728 32.609 6.072 ;
     RECT  33.013 20.544 33.164 20.568 ;
     RECT  33.164 20.544 33.251 20.616 ;
     RECT  32.501 13.296 33.613 19.272 ;
     RECT  33.613 13.296 33.877 19.368 ;
     RECT  33.251 20.544 33.877 20.568 ;
     RECT  33.877 13.296 34.595 20.568 ;
     RECT  32.609 1.728 34.621 5.976 ;
     RECT  34.621 1.728 34.808 6.12 ;
     RECT  34.595 13.296 34.808 20.04 ;
     RECT  34.808 1.728 34.931 20.04 ;
     RECT  34.931 1.728 35.104 19.992 ;
     RECT  35.104 1.728 35.777 6.12 ;
     RECT  35.777 1.728 35.873 5.592 ;
     RECT  35.104 13.296 35.891 19.992 ;
     RECT  35.873 1.152 35.957 5.592 ;
     RECT  35.996 20.544 36.898 20.568 ;
     RECT  35.957 1.728 36.908 5.592 ;
     RECT  35.891 13.296 37.429 19.416 ;
     RECT  36.898 20.544 37.429 20.616 ;
     RECT  36.908 1.728 37.508 5.736 ;
     RECT  37.429 13.296 37.508 20.616 ;
     RECT  37.508 1.728 37.571 20.616 ;
     RECT  37.571 1.728 37.804 20.568 ;
     RECT  37.804 1.728 38.441 5.736 ;
     RECT  38.441 1.728 38.765 5.208 ;
     RECT  37.804 13.296 38.797 20.568 ;
     RECT  38.765 2.256 39.053 5.208 ;
     RECT  38.797 13.104 39.053 20.568 ;
     RECT  38.977 0.192 39.593 0.216 ;
     RECT  39.053 2.256 39.788 5.016 ;
     RECT  39.788 2.16 40.057 5.016 ;
     RECT  40.057 1.728 40.208 5.016 ;
     RECT  39.053 13.872 40.208 20.568 ;
     RECT  40.208 1.728 40.211 20.568 ;
     RECT  40.301 0.576 40.385 0.6 ;
     RECT  40.211 1.728 40.403 19.56 ;
     RECT  40.403 1.728 40.504 19.416 ;
     RECT  40.504 13.344 40.673 19.416 ;
     RECT  40.805 0.192 40.889 0.216 ;
     RECT  40.504 1.728 41.897 3.432 ;
     RECT  41.713 0.528 42.073 0.552 ;
     RECT  40.673 13.872 42.073 19.416 ;
     RECT  40.211 20.544 42.073 20.568 ;
     RECT  42.073 0.192 42.157 0.552 ;
     RECT  42.073 13.872 42.227 20.568 ;
     RECT  42.157 0.528 42.371 0.552 ;
     RECT  42.227 13.872 42.541 19.452 ;
     RECT  42.533 1.104 42.851 1.176 ;
     RECT  41.897 2.256 42.908 3.432 ;
     RECT  42.541 13.824 42.908 19.452 ;
     RECT  42.227 20.544 42.997 20.568 ;
     RECT  42.908 2.148 43.093 19.452 ;
     RECT  43.093 1.728 43.189 19.452 ;
     RECT  42.997 20.544 43.189 20.616 ;
     RECT  43.189 1.728 43.204 20.616 ;
     RECT  43.204 13.728 43.265 20.616 ;
     RECT  43.265 13.728 43.301 20.568 ;
     RECT  43.204 1.728 43.877 3.432 ;
     RECT  43.301 13.728 44.269 19.368 ;
     RECT  43.333 0.192 44.3 0.6 ;
     RECT  44.269 13.344 44.3 19.368 ;
     RECT  43.301 20.544 44.3 20.568 ;
     RECT  44.3 13.344 44.62 20.568 ;
     RECT  44.3 0.192 45.155 1.128 ;
     RECT  45.155 0.192 45.425 0.6 ;
     RECT  43.877 2.256 45.493 3.432 ;
     RECT  45.493 1.68 45.608 3.432 ;
     RECT  44.62 13.344 45.608 19.272 ;
     RECT  45.608 1.68 45.685 19.452 ;
     RECT  44.62 20.544 45.685 20.568 ;
     RECT  45.685 1.68 45.904 20.568 ;
     RECT  45.904 13.872 45.916 20.568 ;
     RECT  45.425 0.192 46.537 0.216 ;
     RECT  45.904 1.68 46.537 3.336 ;
     RECT  46.537 0.192 46.643 3.336 ;
     RECT  45.916 20.544 46.837 20.568 ;
     RECT  46.643 0.192 46.937 0.216 ;
     RECT  45.916 13.872 47.029 19.416 ;
     RECT  46.837 20.544 47.029 20.616 ;
     RECT  47.029 13.872 47.153 20.616 ;
     RECT  46.643 1.728 47.605 3.336 ;
     RECT  47.605 1.152 47.693 3.336 ;
     RECT  47.153 13.872 48.227 20.568 ;
     RECT  47.693 1.728 48.308 3.336 ;
     RECT  48.227 13.872 48.308 19.608 ;
     RECT  48.308 1.728 48.604 19.608 ;
     RECT  48.604 13.872 49.189 19.608 ;
     RECT  48.604 1.728 49.709 3.672 ;
     RECT  49.189 13.872 49.777 19.992 ;
     RECT  49.021 0.576 49.841 0.6 ;
     RECT  49.841 0.192 49.925 0.6 ;
     RECT  49.777 13.872 50.005 20.232 ;
     RECT  49.925 0.576 50.461 0.6 ;
     RECT  49.709 1.728 50.461 3.336 ;
     RECT  50.461 0.576 50.675 3.336 ;
     RECT  50.675 0.576 50.941 0.6 ;
     RECT  50.005 13.872 50.965 20.568 ;
     RECT  50.675 1.728 51.008 3.336 ;
     RECT  50.965 13.872 51.008 20.712 ;
     RECT  51.008 1.728 51.304 20.712 ;
     RECT  51.304 14.112 51.635 20.712 ;
     RECT  51.304 1.728 52.405 3.096 ;
     RECT  51.857 0.192 52.949 0.216 ;
     RECT  51.635 14.112 53.197 20.616 ;
     RECT  52.405 1.632 53.333 3.096 ;
     RECT  53.333 1.104 53.708 3.096 ;
     RECT  53.197 14.112 53.708 21.48 ;
     RECT  53.708 1.104 54.004 21.48 ;
     RECT  54.004 1.104 54.179 3.096 ;
     RECT  54.004 14.112 54.677 21.48 ;
     RECT  54.677 14.352 54.749 21.48 ;
     RECT  54.881 0.192 55.433 0.216 ;
     RECT  54.179 1.68 55.667 3.096 ;
     RECT  55.667 1.728 56.408 3.096 ;
     RECT  54.749 14.448 56.408 21.48 ;
     RECT  56.408 1.728 56.704 21.48 ;
     RECT  56.704 1.728 57.017 1.8 ;
     RECT  57.017 1.728 57.085 1.752 ;
     RECT  57.085 1.104 57.683 1.752 ;
     RECT  56.704 14.448 57.875 21.48 ;
     RECT  56.704 3.072 57.989 3.096 ;
     RECT  57.869 0.192 58.241 0.216 ;
     RECT  57.683 1.68 59.108 1.752 ;
     RECT  57.875 14.448 59.108 20.616 ;
     RECT  59.065 0.528 59.219 0.552 ;
     RECT  59.108 1.68 59.404 20.616 ;
     RECT  59.404 14.448 59.677 20.616 ;
     RECT  59.404 1.68 59.699 1.752 ;
     RECT  59.677 14.448 60.131 20.664 ;
     RECT  60.131 14.448 60.185 20.568 ;
     RECT  59.885 0.576 60.829 0.6 ;
     RECT  59.699 1.728 60.829 1.752 ;
     RECT  60.829 0.576 60.937 1.752 ;
     RECT  60.937 0.576 60.947 2.28 ;
     RECT  60.185 18.816 61.117 20.568 ;
     RECT  61.117 18.816 61.765 20.712 ;
     RECT  60.947 1.728 61.808 2.28 ;
     RECT  60.185 14.448 61.808 17.496 ;
     RECT  61.765 18.816 61.808 20.76 ;
     RECT  61.808 1.728 62.104 20.76 ;
     RECT  60.947 0.576 62.108 0.6 ;
     RECT  62.104 1.728 62.108 2.28 ;
     RECT  62.104 14.352 62.165 17.448 ;
     RECT  62.108 0.576 62.195 2.28 ;
     RECT  62.104 18.96 62.627 20.76 ;
     RECT  62.165 15.696 62.741 17.448 ;
     RECT  62.627 18.96 62.771 20.616 ;
     RECT  62.677 0.192 62.819 0.552 ;
     RECT  62.195 1.728 62.963 2.28 ;
     RECT  62.165 14.352 63.461 14.712 ;
     RECT  62.819 0.528 63.644 0.552 ;
     RECT  62.963 1.728 63.644 1.752 ;
     RECT  63.644 0.528 64.217 1.752 ;
     RECT  62.771 18.96 64.429 20.568 ;
     RECT  64.217 1.728 64.477 1.752 ;
     RECT  63.461 14.352 64.508 14.664 ;
     RECT  62.741 15.792 64.508 17.448 ;
     RECT  64.429 18.768 64.508 20.568 ;
     RECT  64.508 2.148 64.612 20.568 ;
     RECT  64.612 2.256 64.804 20.568 ;
     RECT  64.804 18.768 64.933 20.568 ;
     RECT  64.804 2.256 64.979 2.28 ;
     RECT  64.933 18.768 64.979 20.616 ;
     RECT  64.217 0.528 65.141 0.552 ;
     RECT  64.804 15.792 65.549 16.296 ;
     RECT  65.141 0.192 65.66 0.552 ;
     RECT  64.979 19.968 65.939 20.616 ;
     RECT  65.66 0.192 66.017 1.128 ;
     RECT  64.979 18.96 66.121 18.984 ;
     RECT  64.804 14.448 66.161 14.664 ;
     RECT  66.14 1.152 66.301 1.704 ;
     RECT  66.301 1.152 66.467 1.752 ;
     RECT  65.939 20.544 66.805 20.616 ;
     RECT  66.805 20.544 66.901 20.664 ;
     RECT  66.467 1.152 67.148 1.176 ;
     RECT  66.161 14.64 67.208 14.664 ;
     RECT  65.549 15.792 67.208 15.816 ;
     RECT  64.804 17.424 67.208 17.448 ;
     RECT  66.121 18.576 67.208 18.984 ;
     RECT  66.901 19.968 67.208 20.664 ;
     RECT  67.148 1.104 67.235 1.176 ;
     RECT  67.208 2.148 67.504 20.664 ;
     RECT  67.597 1.68 67.715 1.752 ;
     RECT  67.504 18.96 67.763 20.664 ;
     RECT  67.763 20.544 67.993 20.664 ;
     RECT  67.429 0.528 68.165 0.552 ;
     RECT  68.165 0.192 68.396 0.552 ;
     RECT  67.715 1.68 68.396 1.704 ;
     RECT  68.396 0.192 68.483 1.704 ;
     RECT  67.763 18.96 68.579 19.416 ;
     RECT  67.993 20.544 68.857 20.76 ;
     RECT  68.857 19.968 68.915 20.76 ;
     RECT  68.483 0.192 69.505 0.6 ;
     RECT  68.677 1.728 69.505 1.752 ;
     RECT  69.505 0.192 69.908 1.752 ;
     RECT  67.504 15.792 69.908 15.816 ;
     RECT  67.504 17.424 69.908 17.448 ;
     RECT  68.579 18.96 69.908 18.984 ;
     RECT  68.915 19.968 69.908 20.664 ;
     RECT  69.908 0.192 70.085 20.664 ;
     RECT  70.085 1.728 70.204 20.664 ;
     RECT  70.204 18.768 70.453 18.984 ;
     RECT  70.204 19.968 70.477 20.664 ;
     RECT  70.453 18.96 70.589 18.984 ;
     RECT  70.477 19.968 70.697 20.712 ;
     RECT  70.085 0.192 70.741 0.216 ;
     RECT  70.697 19.968 70.787 20.616 ;
     RECT  70.204 1.728 71.42 2.28 ;
     RECT  71.42 1.104 71.507 2.28 ;
     RECT  70.787 19.968 71.603 20.568 ;
     RECT  71.603 19.968 71.66 20.088 ;
     RECT  71.507 1.68 72.275 2.28 ;
     RECT  71.66 19.392 72.469 20.088 ;
     RECT  72.275 1.728 72.608 2.28 ;
     RECT  72.469 18.768 72.608 20.088 ;
     RECT  72.608 1.728 72.785 20.088 ;
     RECT  72.785 2.016 72.904 20.088 ;
     RECT  72.904 2.016 72.995 2.04 ;
     RECT  72.904 19.968 73.045 20.088 ;
     RECT  73.045 19.968 73.132 20.568 ;
     RECT  73.132 19.968 73.283 19.992 ;
     RECT  73.237 0.576 73.361 0.6 ;
     RECT  75.308 2.148 75.412 19.452 ;
     RECT  75.412 2.418 75.604 19.182 ;
    LAYER M5 ;
     RECT  4.512 0.144 73.272 0.227 ;
     RECT  39.84 0.227 73.272 0.611 ;
     RECT  39.84 0.611 72.984 1.139 ;
     RECT  39.84 1.139 43.848 1.187 ;
     RECT  66.192 1.139 72.984 1.715 ;
     RECT  4.512 0.227 38.712 1.763 ;
     RECT  39.84 1.187 41.832 1.763 ;
     RECT  42.9 1.187 43.848 1.763 ;
     RECT  45.6 1.139 57.432 1.763 ;
     RECT  58.416 1.139 64.968 1.763 ;
     RECT  66.432 1.715 67.704 1.763 ;
     RECT  68.688 1.715 72.984 1.763 ;
     RECT  18.576 1.763 18.912 1.811 ;
     RECT  26.7 1.763 27.144 1.811 ;
     RECT  31.968 1.763 32.904 1.811 ;
     RECT  39.84 1.763 41.352 1.811 ;
     RECT  55.344 1.763 56.904 1.811 ;
     RECT  13.056 1.763 13.512 1.859 ;
     RECT  7.776 1.763 8.112 2.051 ;
     RECT  53.616 1.763 54.012 2.051 ;
     RECT  71.232 1.763 72.984 2.051 ;
     RECT  2.4 2.137 2.52 2.151 ;
     RECT  75.3 2.137 75.42 2.151 ;
     RECT  39.84 1.811 40.512 2.195 ;
     RECT  47.376 1.763 48.888 2.195 ;
     RECT  51 1.763 51.672 2.195 ;
     RECT  55.344 1.811 56.712 2.291 ;
     RECT  61.152 1.763 62.952 2.291 ;
     RECT  64.5 1.763 64.968 2.291 ;
     RECT  71.232 2.051 72.912 2.291 ;
     RECT  5.1 1.763 6.648 2.339 ;
     RECT  48.3 2.195 48.888 2.579 ;
     RECT  37.5 1.763 37.812 2.773 ;
     RECT  15.792 1.763 16.212 2.869 ;
     RECT  17.328 2.821 17.352 2.869 ;
     RECT  18.6 1.811 18.912 2.869 ;
     RECT  20.832 1.763 21.612 2.869 ;
     RECT  37.392 2.773 37.812 2.869 ;
     RECT  31.968 1.811 32.412 2.965 ;
     RECT  22.8 3.013 22.824 3.061 ;
     RECT  24 1.763 24.312 3.061 ;
     RECT  37.344 2.869 37.992 3.107 ;
     RECT  37.344 3.107 37.944 3.157 ;
     RECT  20.832 2.869 21.72 3.203 ;
     RECT  39.072 3.109 39.096 3.251 ;
     RECT  29.04 1.763 29.712 3.253 ;
     RECT  22.8 3.061 22.92 3.347 ;
     RECT  24 3.061 24.744 3.395 ;
     RECT  29.04 3.253 30.216 3.395 ;
     RECT  29.04 3.395 29.712 3.443 ;
     RECT  37.152 3.157 37.944 3.443 ;
     RECT  13.2 1.859 13.512 3.685 ;
     RECT  13.2 3.685 13.8 3.829 ;
     RECT  10.5 1.763 10.812 3.925 ;
     RECT  13.104 3.829 13.8 3.925 ;
     RECT  6.624 2.339 6.648 4.019 ;
     RECT  31.968 2.965 32.76 4.213 ;
     RECT  31.392 4.213 32.76 4.261 ;
     RECT  26.7 1.811 27.012 4.309 ;
     RECT  5.1 2.339 5.412 4.501 ;
     RECT  7.8 2.051 8.112 4.501 ;
     RECT  13.056 3.925 13.8 4.547 ;
     RECT  26.7 4.309 27.192 4.595 ;
     RECT  14.976 2.869 16.212 4.979 ;
     RECT  15.792 4.979 16.212 5.029 ;
     RECT  17.328 2.869 18.912 5.029 ;
     RECT  34.8 1.763 35.112 5.029 ;
     RECT  37.5 3.443 37.944 5.029 ;
     RECT  26.7 4.595 27.012 5.077 ;
     RECT  9.792 3.925 11.016 5.171 ;
     RECT  13.056 4.547 13.608 5.171 ;
     RECT  15.792 5.029 18.912 5.171 ;
     RECT  15.792 5.171 16.632 5.219 ;
     RECT  7.8 4.501 8.808 5.747 ;
     RECT  31.392 4.261 33.048 5.747 ;
     RECT  36.96 5.029 37.944 5.747 ;
     RECT  34.8 5.029 35.208 5.795 ;
     RECT  9.792 5.171 10.968 5.843 ;
     RECT  13.2 5.171 13.608 5.939 ;
     RECT  31.392 5.747 32.712 5.939 ;
     RECT  26.208 5.077 27.012 5.987 ;
     RECT  31.968 5.939 32.712 5.987 ;
     RECT  10.5 5.843 10.968 6.131 ;
     RECT  15.9 5.219 16.632 6.131 ;
     RECT  18.24 5.171 18.912 6.275 ;
     RECT  4.8 4.501 5.412 9.683 ;
     RECT  45.6 1.763 45.912 13.381 ;
     RECT  20.832 3.203 21.612 14.149 ;
     RECT  10.5 6.131 10.812 14.197 ;
     RECT  48.3 2.579 48.612 14.197 ;
     RECT  45.504 13.381 45.912 14.437 ;
     RECT  15.9 6.131 16.212 14.485 ;
     RECT  15.216 14.485 16.212 14.533 ;
     RECT  18.6 6.275 18.912 14.533 ;
     RECT  40.2 2.195 40.512 14.629 ;
     RECT  18.6 14.533 19.032 14.725 ;
     RECT  7.8 5.747 8.112 14.773 ;
     RECT  10.5 14.197 11.544 14.773 ;
     RECT  13.2 5.939 13.512 14.773 ;
     RECT  15.216 14.533 16.344 14.773 ;
     RECT  18.144 14.725 19.032 14.773 ;
     RECT  24 3.395 24.312 14.773 ;
     RECT  40.2 14.629 41.304 14.819 ;
     RECT  13.2 14.773 16.344 15.061 ;
     RECT  17.808 14.773 19.032 15.061 ;
     RECT  7.8 14.773 9.048 15.349 ;
     RECT  10.176 14.773 11.544 15.349 ;
     RECT  55.344 2.291 55.368 15.493 ;
     RECT  56.4 2.291 56.712 15.493 ;
     RECT  31.968 5.987 32.412 15.541 ;
     RECT  55.344 15.493 56.712 15.635 ;
     RECT  20.496 14.149 21.612 15.637 ;
     RECT  31.968 15.541 33.096 15.683 ;
     RECT  40.2 14.819 40.512 15.973 ;
     RECT  31.968 15.683 32.412 16.213 ;
     RECT  45.504 14.437 46.776 16.403 ;
     RECT  20.496 15.637 21.864 16.501 ;
     RECT  37.5 5.747 37.812 16.501 ;
     RECT  40.2 15.973 41.064 16.501 ;
     RECT  20.496 16.501 22.68 16.645 ;
     RECT  29.4 3.443 29.712 16.645 ;
     RECT  29.4 16.645 29.928 16.883 ;
     RECT  31.056 16.213 32.412 16.981 ;
     RECT  29.4 16.883 29.712 17.077 ;
     RECT  36.528 16.501 37.812 17.077 ;
     RECT  42.9 1.763 43.212 17.077 ;
     RECT  47.856 14.197 48.612 17.077 ;
     RECT  31.056 16.981 33.096 17.123 ;
     RECT  23.808 14.773 24.312 17.557 ;
     RECT  40.2 16.501 41.544 17.557 ;
     RECT  45.504 16.403 46.728 17.557 ;
     RECT  47.856 17.077 48.888 17.557 ;
     RECT  20.496 16.645 22.824 17.605 ;
     RECT  23.808 17.557 24.504 17.605 ;
     RECT  56.4 15.635 56.712 17.605 ;
     RECT  13.2 15.061 19.032 17.653 ;
     RECT  42.9 17.077 44.232 17.653 ;
     RECT  45.504 17.557 48.888 17.941 ;
     RECT  5.1 9.683 5.412 18.133 ;
     RECT  40.08 17.557 41.544 18.133 ;
     RECT  26.7 5.987 27.012 18.181 ;
     RECT  29.28 17.077 29.712 18.181 ;
     RECT  20.496 17.605 24.504 18.229 ;
     RECT  39.696 18.133 41.544 18.229 ;
     RECT  42.528 17.653 44.232 18.229 ;
     RECT  51 2.195 51.312 18.229 ;
     RECT  50.88 18.229 51.312 18.469 ;
     RECT  34.8 5.795 35.112 18.517 ;
     RECT  55.344 15.635 55.368 18.517 ;
     RECT  56.4 17.605 56.808 18.517 ;
     RECT  67.2 1.763 67.512 18.565 ;
     RECT  29.04 18.181 29.712 18.661 ;
     RECT  7.8 15.349 11.544 18.757 ;
     RECT  34.656 18.517 35.112 18.757 ;
     RECT  36.192 17.077 38.04 18.757 ;
     RECT  45.504 17.941 49.368 18.757 ;
     RECT  64.5 2.291 64.812 18.757 ;
     RECT  69.9 1.763 70.212 18.757 ;
     RECT  72.6 2.291 72.912 18.757 ;
     RECT  5.1 18.133 6.216 18.805 ;
     RECT  7.8 18.757 11.688 18.805 ;
     RECT  13.008 17.653 19.032 18.805 ;
     RECT  20.496 18.229 24.696 18.805 ;
     RECT  26.7 18.181 27.576 18.805 ;
     RECT  29.04 18.661 29.832 18.805 ;
     RECT  31.056 17.123 32.904 18.805 ;
     RECT  34.656 18.757 38.04 18.805 ;
     RECT  45.216 18.757 49.368 18.805 ;
     RECT  50.88 18.469 52.296 18.805 ;
     RECT  13.008 18.805 19.512 18.853 ;
     RECT  20.496 18.805 25.512 18.853 ;
     RECT  53.7 2.051 54.012 18.997 ;
     RECT  55.344 18.517 56.808 18.997 ;
     RECT  26.7 18.805 29.832 19.141 ;
     RECT  4.656 18.805 11.688 19.189 ;
     RECT  13.008 18.853 25.512 19.189 ;
     RECT  31.056 18.805 38.568 19.237 ;
     RECT  39.696 18.229 44.232 19.237 ;
     RECT  53.7 18.997 56.808 19.237 ;
     RECT  53.7 19.237 56.952 19.333 ;
     RECT  4.512 19.189 25.512 19.381 ;
     RECT  26.7 19.141 30.072 19.381 ;
     RECT  31.056 19.237 44.232 19.381 ;
     RECT  53.568 19.333 56.952 19.381 ;
     RECT  57.936 18.757 57.96 19.381 ;
     RECT  59.1 1.763 59.412 19.381 ;
     RECT  61.8 2.291 62.112 19.381 ;
     RECT  64.5 18.757 64.968 19.381 ;
     RECT  72.48 18.757 72.912 19.381 ;
     RECT  4.512 19.381 25.656 19.429 ;
     RECT  26.7 19.381 44.232 19.429 ;
     RECT  2.4 2.151 2.712 19.449 ;
     RECT  61.8 19.381 63.24 19.449 ;
     RECT  75.3 2.151 75.612 19.449 ;
     RECT  2.4 19.449 2.52 19.463 ;
     RECT  45.216 18.805 52.296 19.463 ;
     RECT  75.3 19.449 75.42 19.463 ;
     RECT  53.568 19.381 59.412 19.525 ;
     RECT  4.512 19.429 44.232 19.957 ;
     RECT  45.216 19.463 51.096 19.957 ;
     RECT  52.08 19.463 52.296 19.957 ;
     RECT  53.568 19.525 59.592 19.957 ;
     RECT  60.576 19.381 60.6 19.957 ;
     RECT  61.8 19.449 61.944 19.957 ;
     RECT  62.928 19.449 63.24 19.957 ;
     RECT  64.224 19.381 64.968 19.957 ;
     RECT  66.384 18.565 67.512 19.957 ;
     RECT  68.544 19.381 68.568 19.957 ;
     RECT  69.9 18.757 70.44 19.957 ;
     RECT  71.712 19.381 72.912 19.957 ;
     RECT  4.512 19.957 51.096 20.533 ;
     RECT  52.08 19.957 61.944 20.533 ;
     RECT  62.928 19.957 73.272 20.533 ;
     RECT  4.512 20.533 73.272 21.456 ;
     RECT  57.84 21.456 57.864 21.491 ;
  END
END hbfd_rly_136_SN_fc_f4
END LIBRARY
